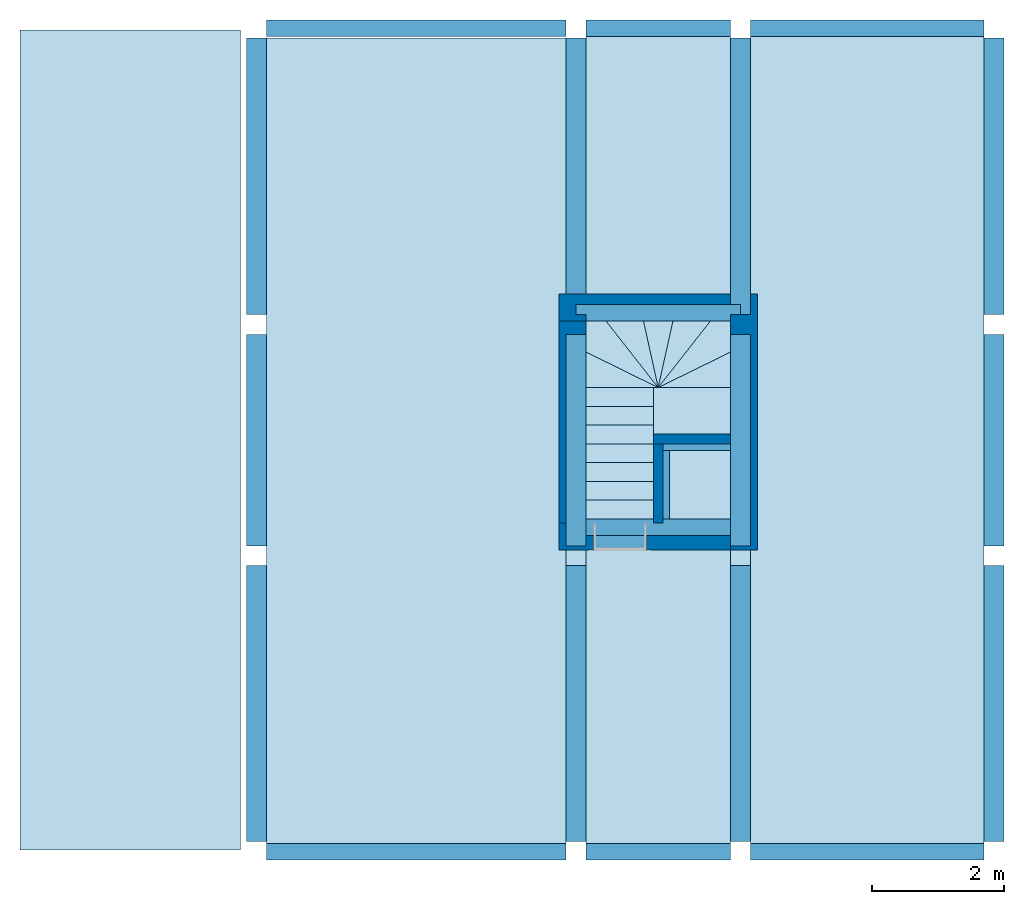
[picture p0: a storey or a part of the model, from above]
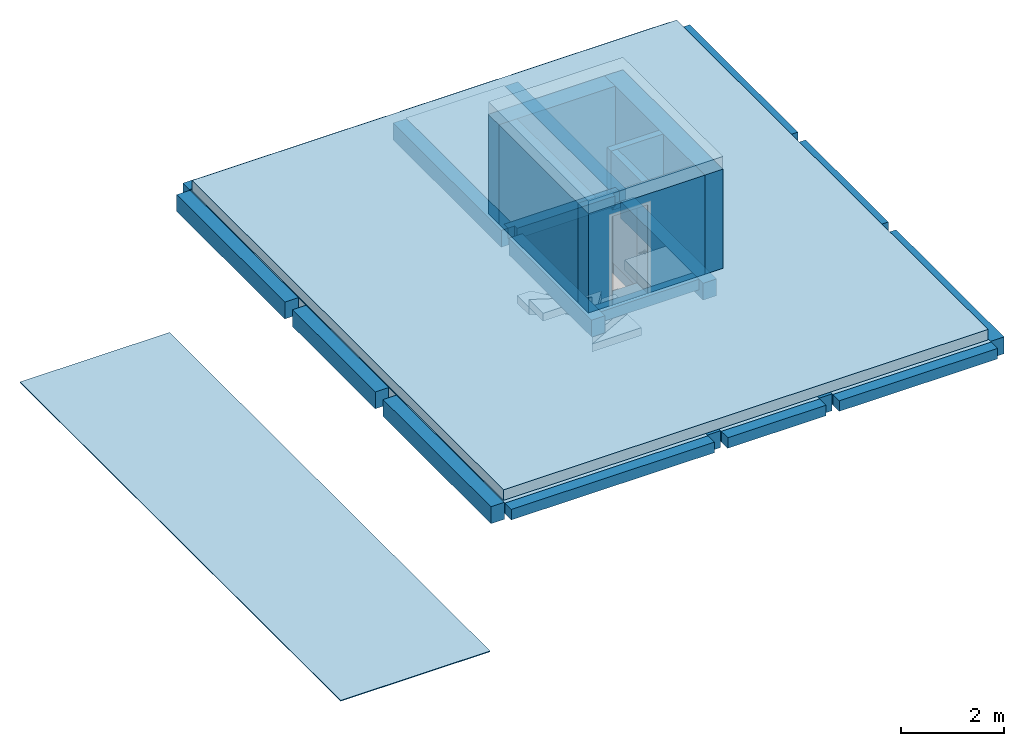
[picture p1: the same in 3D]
Properties of the parts of a building model (IFC2X3), part 1 of 2

# File
Description: ViewDefinition [CoordinationView]
File name: 0001
Time: 2017-05-10T12:55:04
Written by: The EXPRESS Data Manager Version 5.02.0100.07 : 28 Aug 2013
Made in: 20150714_1515(x64) - Exporter 16.0.490.0 - Default UI
Comment: STEP Physical File produced by: The EXPRESS Data Manager Version 5.02.0100.07 : 28 Aug 2013 * Module: EDMstepFileFactory/EDMstandAlone * Creation date: Wed May 10 12:55:04 2017 * Host: w8-delineacion7 * Database: C:\Users\INGENI~1\AppData\Local\Temp\{9E7FC245-E9FD-45FD-B6C2-730FFDB07C34}\ifc * Database version: 5507 * Database creation date: Wed May 10 12:55:01 2017 * Schema: IFC2X3 * Model: DataRepository.ifc * Model creation date: Wed May 10 12:55:01 2017 * Header model: DataRepository.ifc_HeaderModel * Header model creation date: Wed May 10 12:55:01 2017 * EDMuser: sdai-user * EDMgroup: sdai-group * License ID and type: 5605 : Permanent license. Expiry date: * EDMstepFileFactory options: 020000

# IfcProject, 0001
LongName: Nombre de proyecto; Phase: Estado de proyecto

# IfcSite, Default
RefLatitude: 40, 24, 0, 5493; RefLongitude: -3, -40, -59, -880065; RefElevation: 0 m
Otros - Categoría: Información de proyecto; Dirección de proyecto: Introduzca dirección aquí; Estado de proyecto: Estado de proyecto; Fecha de emisión de proyecto: Fecha de emisión; Nombre de cliente: Propietario; Nombre de proyecto: Nombre de proyecto; Número de proyecto: 0001

# IfcBuilding
Pset_BuildingCommon - NumberOfStoreys: 6
Otros - Categoría: Información de proyecto; Dirección de proyecto: Introduzca dirección aquí; Estado de proyecto: Estado de proyecto; Fecha de emisión de proyecto: Fecha de emisión; Nombre de cliente: Propietario; Nombre de proyecto: Nombre de proyecto; Número de proyecto: 0001

# IfcBuildingStorey (6)
Cotas - Altura de cálculo: 0 m
Datos de identidad - Estructura: no; Planta de edificio: yes; Nombre de tipo: Nivel 1
Otros - Categoría: Niveles; Familia: Nivel: Nivel 1; Familia y tipo: Nivel: Nivel 1; ID de tipo: Nivel: Nivel 1; Tipo: Nivel: Nivel 1; Nombre de familia: Nivel
Gráficos - Color: 0; Grosor de línea: 1; Patrón de línea: Trazo punto; Símbolo: Extremo de nivel: Extremo de nivel; Símbolo en extremo 1 por defecto: no; Símbolo en extremo 2 por defecto: yes
Restricciones - Altura base: Punto base del proyecto
Name | LongName = Nombre | Elevation (m) = Alzado (m)
00.ES.CIMENTACIÓN | 00.ES.CIMENTACIÓN | -0.68
01.ES.FORJADO PLANTA BAJA | 01.ES.FORJADO PLANTA BAJA | 0.12
01.AR.PLANTA BAJA ACAB.SUELO | 01.AR.PLANTA BAJA ACAB.SUELO | 0.2
02.ES.PLANTA PRIMERA | 02.ES.PLANTA PRIMERA | 3.45
02.AR.PLANTA PRIMERA ACAB. SUELO | 02.AR.PLANTA PRIMERA ACAB. SUELO | 3.53
03.ES.CUBIERTA | 03.ES.CUBIERTA | 6.78

# IfcBeam: Hormigón-Viga rectangular:250 x 250 mm:155761 (23)
Pset_BeamCommon - IsExternal: no; LoadBearing: yes; Slope: 0 deg; Reference: 250 x 250 mm
Estructura - Activar modelo analítico: yes; Recubrimiento de armadura - Cara inferior: Configuración de recubrimiento de armadura: Revestimiento de armadura 1; Recubrimiento de armadura - Cara superior: Configuración de recubrimiento de armadura: Revestimiento de armadura 1; Recubrimiento de armadura - Otras caras: Configuración de recubrimiento de armadura: Revestimiento de armadura 1; Forma de sección: 0
Otros - Categoría: Armazón estructural; Familia: Hormigón-Viga rectangular: 250 x 250 mm; Familia y tipo: Hormigón-Viga rectangular: 250 x 250 mm; ID de tipo: Hormigón-Viga rectangular: 250 x 250 mm; Tipo: Hormigón-Viga rectangular: 250 x 250 mm; Nombre de familia: Hormigón-Viga rectangular
Posición geométrica - Estado de unión: Ambas uniones activadas; Justificación Y: Origen; Justificación YZ: Uniforme; Justificación Z: Parte superior; Valor de desfase Y: 0 m; Valor de desfase Z: 0 m
Proceso por fases - Fase de creación: Nueva construcción
Restricciones - Desfase de nivel final: 0 m; Desfase de nivel inicial: 0 m; Orientación: Normal; Rotación de sección transversal: 0 deg
Cotas - b: 0.25 m; h: 0.25 m
Datos de identidad - Nombre de tipo: 250 x 250 mm
Name (Hormigón-Viga rectangular:250 x 250 mm:...) | In | Span (m) = Longitud (m) | Área (m2) | Elevación en parte inferior (m) | Elevación en parte superior (m) = Elevación de nivel de referencia (m) | Volumen (m3) | Longitud de corte (m) | Tipo de enlace final = Tipo de enlace inicial | Uso estructural | Nivel de referencia | Plano de trabajo
155414 | 02.ES.PLANTA PRIMERA | 4.24 | 2.18253 | 3.2 | 3.45 | 0.265004 | 4.24006 | Elevación final | Jácena | Nivel: 02.ES.PLANTA PRIMERA | Nivel : 02.ES.PLANTA PRIMERA
155586 | 02.ES.PLANTA PRIMERA | 3.26 | 1.69247 | 3.2 | 3.45 | 0.203746 | 3.25994 | Elevación final | Jácena | Nivel: 02.ES.PLANTA PRIMERA | Nivel : 02.ES.PLANTA PRIMERA
155618 | 02.ES.PLANTA PRIMERA | 4.25 | 2.1875 | 3.2 | 3.45 | 0.265625 | 4.25 | Elevación final | Jácena | Nivel: 02.ES.PLANTA PRIMERA | Nivel : 02.ES.PLANTA PRIMERA
155778 | 02.ES.PLANTA PRIMERA | 3.34 | 1.7325 | 3.2 | 3.45 | 0.20875 | 3.34 | Elevación final | Jácena | Nivel: 02.ES.PLANTA PRIMERA | Nivel : 02.ES.PLANTA PRIMERA
155796 | 02.ES.PLANTA PRIMERA | 4.55 | 2.3375 | 3.2 | 3.45 | 0.284375 | 4.55 | Elevación final | Jácena | Nivel: 02.ES.PLANTA PRIMERA | Nivel : 02.ES.PLANTA PRIMERA
155823 | 02.ES.PLANTA PRIMERA | 2.2 | 1.1625 | 3.2 | 3.45 | 0.1375 | 2.2 | Elevación final | Jácena | Nivel: 02.ES.PLANTA PRIMERA | Nivel : 02.ES.PLANTA PRIMERA
155849 | 02.ES.PLANTA PRIMERA | 3.55 | 1.8375 | 3.2 | 3.45 | 0.221875 | 3.55 | Elevación final | Jácena | Nivel: 02.ES.PLANTA PRIMERA | Nivel : 02.ES.PLANTA PRIMERA
155918 | 02.ES.PLANTA PRIMERA | 3.34 | 1.7325 | 3.2 | 3.45 | 0.20875 | 3.34 | Elevación final | Jácena | Nivel: 02.ES.PLANTA PRIMERA | Nivel : 02.ES.PLANTA PRIMERA
155951 | 02.ES.PLANTA PRIMERA | 4.55 | 2.3375 | 3.2 | 3.45 | 0.284375 | 4.55 | Elevación final | Jácena | Nivel: 02.ES.PLANTA PRIMERA | Nivel : 02.ES.PLANTA PRIMERA
155977 | 02.ES.PLANTA PRIMERA | 2.2 | 1.1625 | 3.2 | 3.45 | 0.1375 | 2.2 | Elevación final | Jácena | Nivel: 02.ES.PLANTA PRIMERA | Nivel : 02.ES.PLANTA PRIMERA
156023 | 02.ES.PLANTA PRIMERA | 3.55 | 1.8375 | 3.2 | 3.45 | 0.221875 | 3.55 | Elevación final | Jácena | Nivel: 02.ES.PLANTA PRIMERA | Nivel : 02.ES.PLANTA PRIMERA
156058 | 02.ES.PLANTA PRIMERA | 2.5 | 1.1625 | 3.2 | 3.45 | 0.1375 | 2.2 |  | Vigueta | Nivel: 02.ES.PLANTA PRIMERA | Nivel : 02.ES.PLANTA PRIMERA
156088 | 02.ES.PLANTA PRIMERA | 2.2 | 1.1625 | 3.2 | 3.45 | 0.1375 | 2.2 | Elevación final | Jácena | Nivel: 02.ES.PLANTA PRIMERA | Nivel : 02.ES.PLANTA PRIMERA
156848 | 03.ES.CUBIERTA | 3.55 | 1.8375 | 6.53 | 6.78 | 0.221875 | 3.55 | Elevación final | Jácena | Nivel: 03.ES.CUBIERTA | Nivel : 03.ES.CUBIERTA
156881 | 03.ES.CUBIERTA | 2.2 | 1.1625 | 6.53 | 6.78 | 0.1375 | 2.2 | Elevación final | Jácena | Nivel: 03.ES.CUBIERTA | Nivel : 03.ES.CUBIERTA
156908 | 03.ES.CUBIERTA | 4.55 | 2.3375 | 6.53 | 6.78 | 0.284375 | 4.55 | Elevación final | Jácena | Nivel: 03.ES.CUBIERTA | Nivel : 03.ES.CUBIERTA
156937 | 03.ES.CUBIERTA | 3.55 | 1.8375 | 6.53 | 6.78 | 0.221875 | 3.55 | Elevación final | Jácena | Nivel: 03.ES.CUBIERTA | Nivel : 03.ES.CUBIERTA
156961 | 03.ES.CUBIERTA | 2.2 | 1.1625 | 6.53 | 6.78 | 0.1375 | 2.2 | Elevación final | Jácena | Nivel: 03.ES.CUBIERTA | Nivel : 03.ES.CUBIERTA
156997 | 03.ES.CUBIERTA | 4.55 | 2.3375 | 6.53 | 6.78 | 0.284375 | 4.55 | Elevación final | Jácena | Nivel: 03.ES.CUBIERTA | Nivel : 03.ES.CUBIERTA
157406 | 03.ES.CUBIERTA | 2.5 | 1.1625 | 6.53 | 6.78 | 0.1375 | 2.2 |  | Vigueta | Nivel: 03.ES.CUBIERTA | Nivel : 03.ES.CUBIERTA
157472 | 03.ES.CUBIERTA | 1.2 | 0.65 | 6.53 | 6.78 | 0.0734375 | 1.175 |  | Otro | Nivel: 03.ES.CUBIERTA | Nivel : 03.ES.CUBIERTA
157499 | 03.ES.CUBIERTA | 1.29 | 0.5825 | 6.53 | 6.78 | 0.065 | 1.04 |  | Otro | Nivel: 03.ES.CUBIERTA | Nivel : 03.ES.CUBIERTA
157592 | 03.ES.CUBIERTA | 2.5 | 1.284 | 6.53 | 6.78 | 0.149125 | 2.5 | Elevación final | Vigueta | Nivel: 03.ES.CUBIERTA | Nivel : 03.ES.CUBIERTA

# IfcBeam: Hormigón-Viga rectangular:300 x 400 mm:155521 (24)
Pset_BeamCommon - IsExternal: no; LoadBearing: yes; Slope: 0 deg; Reference: 300 x 400 mm
Estructura - Activar modelo analítico: yes; Recubrimiento de armadura - Cara inferior: Configuración de recubrimiento de armadura: Revestimiento de armadura 1; Recubrimiento de armadura - Cara superior: Configuración de recubrimiento de armadura: Revestimiento de armadura 1; Recubrimiento de armadura - Otras caras: Configuración de recubrimiento de armadura: Revestimiento de armadura 1; Tipo de enlace final: Elevación final; Tipo de enlace inicial: Elevación final; Uso estructural: Jácena; Forma de sección: 0
Otros - Categoría: Armazón estructural; Familia: Hormigón-Viga rectangular: 300 x 400 mm; Familia y tipo: Hormigón-Viga rectangular: 300 x 400 mm; ID de tipo: Hormigón-Viga rectangular: 300 x 400 mm; Tipo: Hormigón-Viga rectangular: 300 x 400 mm; Nombre de familia: Hormigón-Viga rectangular
Posición geométrica - Estado de unión: Ambas uniones activadas; Justificación Y: Origen; Justificación YZ: Uniforme; Justificación Z: Parte superior; Valor de desfase Y: 0 m; Valor de desfase Z: 0 m
Proceso por fases - Fase de creación: Nueva construcción
Restricciones - Desfase de nivel final: 0 m; Desfase de nivel inicial: 0 m; Orientación: Normal; Rotación de sección transversal: 0 deg
Cotas - b: 0.3 m; h: 0.4 m
Datos de identidad - Nombre de tipo: 300 x 400 mm
Name (Hormigón-Viga rectangular:300 x 400 mm:...) | In | Span (m) = Longitud (m) | Área (m2) | Elevación en parte inferior (m) | Elevación en parte superior (m) = Elevación de nivel de referencia (m) | Volumen (m3) | Longitud de corte (m) | Nivel de referencia | Plano de trabajo
155697 | 02.ES.PLANTA PRIMERA | 4.24 | 3.05304 | 3.05 | 3.45 | 0.502807 | 4.19006 | Nivel: 02.ES.PLANTA PRIMERA | Nivel : 02.ES.PLANTA PRIMERA
155699 | 02.ES.PLANTA PRIMERA | 3.26 | 2.36696 | 3.05 | 3.45 | 0.385193 | 3.20994 | Nivel: 02.ES.PLANTA PRIMERA | Nivel : 02.ES.PLANTA PRIMERA
155701 | 02.ES.PLANTA PRIMERA | 4.25 | 3.06 | 3.05 | 3.45 | 0.504 | 4.2 | Nivel: 02.ES.PLANTA PRIMERA | Nivel : 02.ES.PLANTA PRIMERA
155718 | 02.ES.PLANTA PRIMERA | 4.24 | 3.05304 | 3.05 | 3.45 | 0.502807 | 4.19006 | Nivel: 02.ES.PLANTA PRIMERA | Nivel : 02.ES.PLANTA PRIMERA
155720 | 02.ES.PLANTA PRIMERA | 3.26 | 2.36696 | 3.05 | 3.45 | 0.385193 | 3.20994 | Nivel: 02.ES.PLANTA PRIMERA | Nivel : 02.ES.PLANTA PRIMERA
155722 | 02.ES.PLANTA PRIMERA | 4.25 | 3.06 | 3.05 | 3.45 | 0.504 | 4.2 | Nivel: 02.ES.PLANTA PRIMERA | Nivel : 02.ES.PLANTA PRIMERA
155730 | 02.ES.PLANTA PRIMERA | 4.24 | 3.05304 | 3.05 | 3.45 | 0.502807 | 4.19006 | Nivel: 02.ES.PLANTA PRIMERA | Nivel : 02.ES.PLANTA PRIMERA
155732 | 02.ES.PLANTA PRIMERA | 3.26 | 2.36696 | 3.05 | 3.45 | 0.385193 | 3.20994 | Nivel: 02.ES.PLANTA PRIMERA | Nivel : 02.ES.PLANTA PRIMERA
155734 | 02.ES.PLANTA PRIMERA | 4.25 | 3.06 | 3.05 | 3.45 | 0.504 | 4.2 | Nivel: 02.ES.PLANTA PRIMERA | Nivel : 02.ES.PLANTA PRIMERA
155746 | 02.ES.PLANTA PRIMERA | 4.24 | 3.05304 | 3.05 | 3.45 | 0.502807 | 4.19006 | Nivel: 02.ES.PLANTA PRIMERA | Nivel : 02.ES.PLANTA PRIMERA
155748 | 02.ES.PLANTA PRIMERA | 3.26 | 2.36696 | 3.05 | 3.45 | 0.385193 | 3.20994 | Nivel: 02.ES.PLANTA PRIMERA | Nivel : 02.ES.PLANTA PRIMERA
155750 | 02.ES.PLANTA PRIMERA | 4.25 | 3.06 | 3.05 | 3.45 | 0.504 | 4.2 | Nivel: 02.ES.PLANTA PRIMERA | Nivel : 02.ES.PLANTA PRIMERA
157061 | 03.ES.CUBIERTA | 4.19 | 3.05304 | 6.38 | 6.78 | 0.502807 | 4.19006 | Nivel: 03.ES.CUBIERTA | Nivel : 03.ES.CUBIERTA
157082 | 03.ES.CUBIERTA | 3.21 | 2.36696 | 6.38 | 6.78 | 0.385193 | 3.20994 | Nivel: 03.ES.CUBIERTA | Nivel : 03.ES.CUBIERTA
157100 | 03.ES.CUBIERTA | 4.2 | 3.06 | 6.38 | 6.78 | 0.504 | 4.2 | Nivel: 03.ES.CUBIERTA | Nivel : 03.ES.CUBIERTA
157162 | 03.ES.CUBIERTA | 4.19 | 3.05304 | 6.38 | 6.78 | 0.502807 | 4.19006 | Nivel: 03.ES.CUBIERTA | Nivel : 03.ES.CUBIERTA
157164 | 03.ES.CUBIERTA | 3.21 | 2.36696 | 6.38 | 6.78 | 0.385193 | 3.20994 | Nivel: 03.ES.CUBIERTA | Nivel : 03.ES.CUBIERTA
157166 | 03.ES.CUBIERTA | 4.2 | 3.06 | 6.38 | 6.78 | 0.498188 | 4.2 | Nivel: 03.ES.CUBIERTA | Nivel : 03.ES.CUBIERTA
157176 | 03.ES.CUBIERTA | 4.19 | 3.05304 | 6.38 | 6.78 | 0.502807 | 4.19006 | Nivel: 03.ES.CUBIERTA | Nivel : 03.ES.CUBIERTA
157178 | 03.ES.CUBIERTA | 3.21 | 2.36696 | 6.38 | 6.78 | 0.385193 | 3.20994 | Nivel: 03.ES.CUBIERTA | Nivel : 03.ES.CUBIERTA
157180 | 03.ES.CUBIERTA | 4.2 | 3.06 | 6.38 | 6.78 | 0.498188 | 4.2 | Nivel: 03.ES.CUBIERTA | Nivel : 03.ES.CUBIERTA
157188 | 03.ES.CUBIERTA | 4.19 | 3.05304 | 6.38 | 6.78 | 0.502807 | 4.19006 | Nivel: 03.ES.CUBIERTA | Nivel : 03.ES.CUBIERTA
157190 | 03.ES.CUBIERTA | 3.21 | 2.36696 | 6.38 | 6.78 | 0.385193 | 3.20994 | Nivel: 03.ES.CUBIERTA | Nivel : 03.ES.CUBIERTA
157192 | 03.ES.CUBIERTA | 4.2 | 3.06 | 6.38 | 6.78 | 0.504 | 4.2 | Nivel: 03.ES.CUBIERTA | Nivel : 03.ES.CUBIERTA

# IfcBeam: Hormigón-Viga rectangular:600 x 700 mm:151253 (31)
In: 00.ES.CIMENTACIÓN
Material: Hormigón - Hormigón moldeado in situ
Pset_BeamCommon - IsExternal: no; LoadBearing: yes; Reference: 600 x 700 mm; Slope: 0 deg
Cotas - Elevación en parte inferior: -1.38 m; Elevación en parte superior: -0.68 m; b: 0.6 m; h: 0.7 m
Estructura - Activar modelo analítico: yes; Recubrimiento de armadura - Cara inferior: Configuración de recubrimiento de armadura: Revestimiento de armadura 1; Recubrimiento de armadura - Cara superior: Configuración de recubrimiento de armadura: Revestimiento de armadura 1; Recubrimiento de armadura - Otras caras: Configuración de recubrimiento de armadura: Revestimiento de armadura 1; Uso estructural: Otro; Forma de sección: 0
Otros - Categoría: Armazón estructural; Familia: Hormigón-Viga rectangular: 600 x 700 mm; Familia y tipo: Hormigón-Viga rectangular: 600 x 700 mm; ID de tipo: Hormigón-Viga rectangular: 600 x 700 mm; Tipo: Hormigón-Viga rectangular: 600 x 700 mm; Nombre de familia: Hormigón-Viga rectangular
Posición geométrica - Estado de unión: Ambas uniones activadas; Justificación Y: Origen; Justificación YZ: Uniforme; Justificación Z: Parte superior; Valor de desfase Y: 0 m; Valor de desfase Z: 0 m
Proceso por fases - Fase de creación: Nueva construcción
Restricciones - Desfase de nivel final: 0 m; Desfase de nivel inicial: 0 m; Elevación de nivel de referencia: -0.68 m; Nivel de referencia: Nivel: 00.ES.CIMENTACIÓN; Orientación: Normal; Plano de trabajo: Nivel : 00.ES.CIMENTACIÓN; Rotación de sección transversal: 0 deg
Datos de identidad - Nombre de tipo: 600 x 700 mm
Name (Hormigón-Viga rectangular:600 x 700 mm:...) | Span (m) = Longitud (m) | Área (m2) | Volumen (m3) | Longitud de corte (m)
151318 | 2.35 | 3.475 | 0.987 | 2.35
151368 | 1 | 1.72 | 0.42 | 1
151405 | 3.35 | 4.775 | 1.407 | 3.35
151619 | 2.265 | 3.3645 | 0.9513 | 2.265
151684 | 3.29 | 4.69708 | 1.38183 | 3.29006
151724 | 2.309 | 3.42292 | 0.970174 | 2.30994
151781 | 3.3 | 4.71 | 1.386 | 3.3
151873 | 2.35 | 3.475 | 0.987 | 2.35
151875 | 1 | 1.72 | 0.42 | 1
151877 | 3.35 | 4.775 | 1.407 | 3.35
151879 | 2.265 | 3.3645 | 0.9513 | 2.265
151904 | 2.35 | 3.475 | 0.987 | 2.35
151906 | 1 | 1.72 | 0.42 | 1
151908 | 3.35 | 4.775 | 1.407 | 3.35
151910 | 2.265 | 3.3645 | 0.9513 | 2.265
151935 | 2.35 | 3.475 | 0.987 | 2.35
151937 | 1 | 1.72 | 0.42 | 1
151939 | 3.35 | 4.775 | 1.407 | 3.35
151941 | 2.265 | 3.3645 | 0.9513 | 2.265
151996 | 3.29 | 4.30708 | 1.25583 | 2.99006
151998 | 2.309 | 3.03292 | 0.844174 | 2.00994
152000 | 3.3 | 4.32 | 1.26 | 3
152021 | 3.29 | 4.30708 | 1.25583 | 2.99006
152023 | 2.309 | 3.03292 | 0.844174 | 2.00994
152025 | 3.3 | 4.32 | 1.26 | 3
152046 | 3.29 | 4.30708 | 1.25583 | 2.99006
152048 | 2.309 | 3.03292 | 0.844174 | 2.00994
152050 | 3.3 | 4.32 | 1.26 | 3
152073 | 3.29 | 4.30708 | 1.25583 | 2.99006
152075 | 2.309 | 3.03292 | 0.844174 | 2.00994
152077 | 3.3 | 4.32 | 1.26 | 3

# IfcColumn: 250 x 250 mm (4)
In: 00.ES.CIMENTACIÓN
Type - ElementType: 250 x 250 mm; PredefinedType: COLUMN
Type - Cotas - b: 0.25 m; h: 0.25 m
Type - Datos de identidad - Nombre de tipo: 250 x 250 mm
Type - Estructura - Forma de sección: 0
Type - Otros - Categoría: Pilares estructurales; Nombre de familia: Pilar rectangular hormigón
Pset_ColumnCommon - IsExternal: no; LoadBearing: yes; Slope: 0 deg; Reference: 250 x 250 mm
Cotas - Área: 2.1275 m2; Longitud: 4.13 m; Volumen: 0.258125 m3
Estructura - Activar modelo analítico: yes; Recubrimiento de armadura - Cara inferior: Configuración de recubrimiento de armadura: Revestimiento de armadura 1; Recubrimiento de armadura - Cara superior: Configuración de recubrimiento de armadura: Revestimiento de armadura 1; Recubrimiento de armadura - Otras caras: Configuración de recubrimiento de armadura: Revestimiento de armadura 1
Otros - Familia: Pilar rectangular hormigón: 250 x 250 mm; Familia y tipo: Pilar rectangular hormigón: 250 x 250 mm; ID de tipo: Pilar rectangular hormigón: 250 x 250 mm; Tipo: Pilar rectangular hormigón: 250 x 250 mm
Proceso por fases - Fase de creación: Nueva construcción
Restricciones - Se mueve con rejillas: yes; Nivel: Nivel: 00.ES.CIMENTACIÓN; Delimitación de habitación: yes; Desfase de base: 0 m; Desfase superior: 0 m; Estilo de pilar: Vertical; Nivel base: Nivel: 00.ES.CIMENTACIÓN; Nivel superior: Nivel: 02.ES.PLANTA PRIMERA
Name (Pilar rectangular hormigón:250 x 250 mm:...) | Marca de ubicación de pilar
153593 | A-1
153595 | A-2
153597 | A-3
153599 | A-4

# IfcColumn: 300 x 300 mm (32)
Type - ElementType: 300 x 300 mm; PredefinedType: COLUMN
Type - Cotas - b: 0.3 m; h: 0.3 m
Type - Datos de identidad - Nombre de tipo: 300 x 300 mm
Type - Estructura - Forma de sección: 0
Type - Otros - Categoría: Pilares estructurales; Nombre de familia: Pilar rectangular hormigón
Pset_ColumnCommon - IsExternal: no; LoadBearing: yes; Slope: 0 deg; Reference: 300 x 300 mm
Estructura - Activar modelo analítico: yes; Recubrimiento de armadura - Cara inferior: Configuración de recubrimiento de armadura: Revestimiento de armadura 1; Recubrimiento de armadura - Cara superior: Configuración de recubrimiento de armadura: Revestimiento de armadura 1; Recubrimiento de armadura - Otras caras: Configuración de recubrimiento de armadura: Revestimiento de armadura 1
Otros - Familia: Pilar rectangular hormigón: 300 x 300 mm; Familia y tipo: Pilar rectangular hormigón: 300 x 300 mm; ID de tipo: Pilar rectangular hormigón: 300 x 300 mm; Tipo: Pilar rectangular hormigón: 300 x 300 mm
Proceso por fases - Fase de creación: Nueva construcción
Restricciones - Se mueve con rejillas: yes; Delimitación de habitación: yes; Desfase de base: 0 m; Desfase superior: 0 m; Estilo de pilar: Vertical
Name (Pilar rectangular hormigón:300 x 300 mm:...) | In | Área (m2) | Longitud (m) | Volumen (m3) | Nivel = Nivel base | Nivel superior | Marca de ubicación de pilar
153704 | 00.ES.CIMENTACIÓN | 2.568 | 4.13 | 0.3717 | Nivel: 00.ES.CIMENTACIÓN | Nivel: 02.ES.PLANTA PRIMERA | B-1
153706 | 00.ES.CIMENTACIÓN | 2.568 | 4.13 | 0.3717 | Nivel: 00.ES.CIMENTACIÓN | Nivel: 02.ES.PLANTA PRIMERA | C-1
153708 | 00.ES.CIMENTACIÓN | 2.568 | 4.13 | 0.3717 | Nivel: 00.ES.CIMENTACIÓN | Nivel: 02.ES.PLANTA PRIMERA | D-1
153710 | 00.ES.CIMENTACIÓN | 2.568 | 4.13 | 0.3717 | Nivel: 00.ES.CIMENTACIÓN | Nivel: 02.ES.PLANTA PRIMERA | E-1
153712 | 00.ES.CIMENTACIÓN | 2.568 | 4.13 | 0.3717 | Nivel: 00.ES.CIMENTACIÓN | Nivel: 02.ES.PLANTA PRIMERA | B-2
153714 | 00.ES.CIMENTACIÓN | 2.568 | 4.13 | 0.3717 | Nivel: 00.ES.CIMENTACIÓN | Nivel: 02.ES.PLANTA PRIMERA | C-2
153716 | 00.ES.CIMENTACIÓN | 2.568 | 4.13 | 0.3717 | Nivel: 00.ES.CIMENTACIÓN | Nivel: 02.ES.PLANTA PRIMERA | D-2
153718 | 00.ES.CIMENTACIÓN | 2.568 | 4.13 | 0.3717 | Nivel: 00.ES.CIMENTACIÓN | Nivel: 02.ES.PLANTA PRIMERA | E-2
153720 | 00.ES.CIMENTACIÓN | 2.568 | 4.13 | 0.3717 | Nivel: 00.ES.CIMENTACIÓN | Nivel: 02.ES.PLANTA PRIMERA | B-3
153722 | 00.ES.CIMENTACIÓN | 2.568 | 4.13 | 0.3717 | Nivel: 00.ES.CIMENTACIÓN | Nivel: 02.ES.PLANTA PRIMERA | C-3
153724 | 00.ES.CIMENTACIÓN | 2.568 | 4.13 | 0.3717 | Nivel: 00.ES.CIMENTACIÓN | Nivel: 02.ES.PLANTA PRIMERA | D-3
153726 | 00.ES.CIMENTACIÓN | 2.568 | 4.13 | 0.3717 | Nivel: 00.ES.CIMENTACIÓN | Nivel: 02.ES.PLANTA PRIMERA | E-3
153728 | 00.ES.CIMENTACIÓN | 2.568 | 4.13 | 0.3717 | Nivel: 00.ES.CIMENTACIÓN | Nivel: 02.ES.PLANTA PRIMERA | B-4
153730 | 00.ES.CIMENTACIÓN | 2.568 | 4.13 | 0.3717 | Nivel: 00.ES.CIMENTACIÓN | Nivel: 02.ES.PLANTA PRIMERA | C-4
153732 | 00.ES.CIMENTACIÓN | 2.568 | 4.13 | 0.3717 | Nivel: 00.ES.CIMENTACIÓN | Nivel: 02.ES.PLANTA PRIMERA | D-4
153734 | 00.ES.CIMENTACIÓN | 2.568 | 4.13 | 0.3717 | Nivel: 00.ES.CIMENTACIÓN | Nivel: 02.ES.PLANTA PRIMERA | E-4
156709 | 02.ES.PLANTA PRIMERA | 2.088 | 3.33 | 0.2997 | Nivel: 02.ES.PLANTA PRIMERA | Nivel: 03.ES.CUBIERTA | B-1
156711 | 02.ES.PLANTA PRIMERA | 2.088 | 3.33 | 0.2997 | Nivel: 02.ES.PLANTA PRIMERA | Nivel: 03.ES.CUBIERTA | C-1
156713 | 02.ES.PLANTA PRIMERA | 2.088 | 3.33 | 0.2997 | Nivel: 02.ES.PLANTA PRIMERA | Nivel: 03.ES.CUBIERTA | D-1
156715 | 02.ES.PLANTA PRIMERA | 2.088 | 3.33 | 0.2997 | Nivel: 02.ES.PLANTA PRIMERA | Nivel: 03.ES.CUBIERTA | E-1
156717 | 02.ES.PLANTA PRIMERA | 2.088 | 3.33 | 0.2997 | Nivel: 02.ES.PLANTA PRIMERA | Nivel: 03.ES.CUBIERTA | B-2
156719 | 02.ES.PLANTA PRIMERA | 2.088 | 3.33 | 0.2997 | Nivel: 02.ES.PLANTA PRIMERA | Nivel: 03.ES.CUBIERTA | C-2
156721 | 02.ES.PLANTA PRIMERA | 2.088 | 3.33 | 0.2997 | Nivel: 02.ES.PLANTA PRIMERA | Nivel: 03.ES.CUBIERTA | D-2
156723 | 02.ES.PLANTA PRIMERA | 2.088 | 3.33 | 0.2997 | Nivel: 02.ES.PLANTA PRIMERA | Nivel: 03.ES.CUBIERTA | E-2
156725 | 02.ES.PLANTA PRIMERA | 2.088 | 3.33 | 0.2997 | Nivel: 02.ES.PLANTA PRIMERA | Nivel: 03.ES.CUBIERTA | B-3
156727 | 02.ES.PLANTA PRIMERA | 2.088 | 3.33 | 0.2997 | Nivel: 02.ES.PLANTA PRIMERA | Nivel: 03.ES.CUBIERTA | C-3
156729 | 02.ES.PLANTA PRIMERA | 2.088 | 3.33 | 0.2997 | Nivel: 02.ES.PLANTA PRIMERA | Nivel: 03.ES.CUBIERTA | D-3
156731 | 02.ES.PLANTA PRIMERA | 2.088 | 3.33 | 0.2997 | Nivel: 02.ES.PLANTA PRIMERA | Nivel: 03.ES.CUBIERTA | E-3
156733 | 02.ES.PLANTA PRIMERA | 2.088 | 3.33 | 0.2997 | Nivel: 02.ES.PLANTA PRIMERA | Nivel: 03.ES.CUBIERTA | B-4
156735 | 02.ES.PLANTA PRIMERA | 2.088 | 3.33 | 0.2997 | Nivel: 02.ES.PLANTA PRIMERA | Nivel: 03.ES.CUBIERTA | C-4
156737 | 02.ES.PLANTA PRIMERA | 2.088 | 3.33 | 0.2997 | Nivel: 02.ES.PLANTA PRIMERA | Nivel: 03.ES.CUBIERTA | D-4
156739 | 02.ES.PLANTA PRIMERA | 2.088 | 3.33 | 0.2997 | Nivel: 02.ES.PLANTA PRIMERA | Nivel: 03.ES.CUBIERTA | E-4

# IfcCovering: Techo compuesto:Falso techo continuo de placa de yeso laminado (16)
PredefinedType: CEILING; Material: Metal - Perfiles de acero galvanizado 0.045 m, Placa de yeso laminado 0.015 m
Pset_CoveringCommon - Reference: Falso techo continuo de placa de yeso laminado; Finish: Placa de yeso laminado;; TotalThickness: 0.06 m
Otros - Categoría: Techos; Familia: Techo compuesto: Falso techo continuo de placa de yeso laminado; Familia y tipo: Techo compuesto: Falso techo continuo de placa de yeso laminado; ID de tipo: Techo compuesto: Falso techo continuo de placa de yeso laminado; Tipo: Techo compuesto: Falso techo continuo de placa de yeso laminado; Nombre de familia: Techo compuesto
Proceso por fases - Fase de creación: Nueva construcción
Restricciones - Delimitación de habitación: yes; Desfase de altura desde nivel: 2.6 m
Construcción - Grosor: 0.06 m
Datos de identidad - Nombre de tipo: Falso techo continuo de placa de yeso laminado
Gráficos - Color de relleno de detalle bajo: 0
Propiedades analíticas - Aspereza: 3; Absortancia: 0.7
Name (Techo compuesto:Falso techo continuo de placa de yeso laminado:...) | In | Área (m2) | Perímetro (m) | Volumen (m3) | Nivel
181849 | 01.AR.PLANTA BAJA ACAB.SUELO | 4.7957 | 8.76 | 0.287742 | Nivel: 01.AR.PLANTA BAJA ACAB.SUELO
181857 | 01.AR.PLANTA BAJA ACAB.SUELO | 28.821 | 22.99 | 1.72926 | Nivel: 01.AR.PLANTA BAJA ACAB.SUELO
181865 | 01.AR.PLANTA BAJA ACAB.SUELO | 15.3029 | 15.673 | 0.918174 | Nivel: 01.AR.PLANTA BAJA ACAB.SUELO
181873 | 01.AR.PLANTA BAJA ACAB.SUELO | 5.86229 | 9.74304 | 0.351738 | Nivel: 01.AR.PLANTA BAJA ACAB.SUELO
181881 | 01.AR.PLANTA BAJA ACAB.SUELO | 2.7125 | 6.84 | 0.16275 | Nivel: 01.AR.PLANTA BAJA ACAB.SUELO
181889 | 01.AR.PLANTA BAJA ACAB.SUELO | 56.7697 | 33.573 | 3.40618 | Nivel: 01.AR.PLANTA BAJA ACAB.SUELO
181897 | 01.AR.PLANTA BAJA ACAB.SUELO | 56.7697 | 33.573 | 3.40618 | Nivel: 01.AR.PLANTA BAJA ACAB.SUELO
181914 | 01.AR.PLANTA BAJA ACAB.SUELO | 6.24275 | 10.89 | 0.374565 | Nivel: 01.AR.PLANTA BAJA ACAB.SUELO
182334 | 02.AR.PLANTA PRIMERA ACAB. SUELO | 23.9871 | 21.293 | 1.43923 | Nivel: 02.AR.PLANTA PRIMERA ACAB. SUELO
182344 | 02.AR.PLANTA PRIMERA ACAB. SUELO | 5.94334 | 9.80304 | 0.3566 | Nivel: 02.AR.PLANTA PRIMERA ACAB. SUELO
182404 | 02.AR.PLANTA PRIMERA ACAB. SUELO | 2.75 | 6.9 | 0.165 | Nivel: 02.AR.PLANTA PRIMERA ACAB. SUELO
182412 | 02.AR.PLANTA PRIMERA ACAB. SUELO | 15.7874 | 15.9401 | 0.947245 | Nivel: 02.AR.PLANTA PRIMERA ACAB. SUELO
182420 | 02.AR.PLANTA PRIMERA ACAB. SUELO | 30.1591 | 22.6401 | 1.80955 | Nivel: 02.AR.PLANTA PRIMERA ACAB. SUELO
182428 | 02.AR.PLANTA PRIMERA ACAB. SUELO | 8.957 | 12.06 | 0.53742 | Nivel: 02.AR.PLANTA PRIMERA ACAB. SUELO
190506 | 02.AR.PLANTA PRIMERA ACAB. SUELO | 17.2985 | 23.048 | 1.03791 | Nivel: 02.AR.PLANTA PRIMERA ACAB. SUELO
191344 | 02.AR.PLANTA PRIMERA ACAB. SUELO | 15.2408 | 15.643 | 0.914447 | Nivel: 02.AR.PLANTA PRIMERA ACAB. SUELO

# IfcCurtainWall: Muro cortina:Muro cortina - simple (5)
In: 01.AR.PLANTA BAJA ACAB.SUELO
Type - Construcción - Función: Exterior; Condición de unión: Sin definir; Incrustar automáticamente: no
Type - Datos de identidad - Nombre de tipo: Muro cortina - simple; Nota clave: Mc.4
Type - Otros - Categoría: Muros; Nombre de familia: Muro cortina
Type - Rejilla horizontal - Ajustar para tamaño de montante: no; Diseño: Ninguno
Type - Rejilla vertical - Ajustar para tamaño de montante: no; Diseño: Ninguno
Pset_CurtainWallCommon - IsExternal: yes; Reference: Muro cortina - simple
Estructura - Activar modelo analítico: no; Estructura: no; Uso estructural: No portante
Otros - Familia: Muro cortina: Muro cortina - simple; Familia y tipo: Muro cortina: Muro cortina - simple; ID de tipo: Muro cortina: Muro cortina - simple; Tipo: Muro cortina: Muro cortina - simple
Proceso por fases - Fase de creación: Nueva construcción
Rejilla horizontal - Desfase: 0 m; Ángulo: 0 deg; Justificación: Inicio; Número: 4; sets with these values: 2
Restricciones - Delimitación de habitación: yes; Desfase de base: 0 m; Desfase superior: 0 m; La base está enlazada: no; La parte superior está enlazada: no; Relacionado con masa: no; Restricción de base: Nivel: 01.AR.PLANTA BAJA ACAB.SUELO; Altura desconectada: 3 m
Name (Muro cortina:Muro cortina - simple:...) | Área (m2) | Longitud (m)
193462 | 9.75 | 3.455
193901 | 12.7202 | 4.24006
194046 | 9.77982 | 3.25994
194191 | 12.75 | 4.25
194256 | 9.75 | 3.455

# IfcDoor: 1400 x 2100mm, Puerta practicable de entrada, 2 hojas:1400 x 2100mm:189911
In: 01.AR.PLANTA BAJA ACAB.SUELO
Type - ParameterTakesPrecedence: no; Sizeable: no; Material: Dark Oak, Vidrio
Type - Construcción - Función: Exterior; Cierre de muro: Por anfitrión
Type - Cotas - Altura: 2.1 m; Altura aproximada: 2.1 m; Anchura: 1.4 m; Anchura aproximada: 1.4 m; Anchura de cubrejuntas: 0.035 m; Anchura de marco: 0.05 m; Anchura de marco de panel: 0.1 m; Anchura de montante secundario: 0.07 m; Anchura de puerta con tirador: 0.7 m; Anchura de puerta sin tirador: 0.7 m; Grosor de cubrejuntas: 0.005 m; Grosor de marco: 0.045 m
Type - Datos de identidad - Marca de tipo: 9; Nombre de tipo: 1400 x 2100mm; Número OmniClass: 23.30.10.00; Título OmniClass: Doors
Type - Materiales y acabados - Material de marco: Dark Oak
Type - Otros - Categoría: Puertas; Altura Hoja: 2.07 m; Anchura de panel de puerta con tirador: 0.685 m; Anchura de panel de puerta sin tirador: 0.685 m; Desfase: 0.015 m; Nombre de familia: Puerta practicable de entrada, 2 hojas; w: 0.015 m
Type - Propiedades analíticas - Coeficiente de incremento de calor solar: 0; Transmitancia de luz visual: 0; Coeficiente de transferencia de calor (U): 3.7021; Construcción analítica: Metal; Resistencia térmica (R): 0.270117
OverallHeight: 2.1 m; OverallWidth: 1.4 m
Pset_DoorCommon - IsExternal: yes; Reference: 1400 x 2100mm; ThermalTransmittance: 3.7021 kg/K/s3
Cotas - Área: 4.98891 m2; Volumen: 0.0755501 m3
Datos de identidad - Marca: 22
Otros - ID de anfitrión: Muro básico: F3.2; Altura de extremo inicial: 2.1 m; Familia: Puerta practicable de entrada, 2 hojas: 1400 x 2100mm; Familia y tipo: Puerta practicable de entrada, 2 hojas: 1400 x 2100mm; ID de tipo: Puerta practicable de entrada, 2 hojas: 1400 x 2100mm; Tipo: Puerta practicable de entrada, 2 hojas: 1400 x 2100mm
Proceso por fases - Fase de creación: Nueva construcción
Restricciones - Nivel: Nivel: 01.AR.PLANTA BAJA ACAB.SUELO; Altura de antepecho: 0 m

# IfcDoor: 200 x 205 cm - 8 Vidrios repartidos (3)
Type - ParameterTakesPrecedence: no; Sizeable: no; Material: Aberturas - Picaporte Entrada, Aberturas - Vidrio, Dark Oak
Type - Construcción - Función: Interior; Cierre de muro: Por anfitrión
Type - Cotas - Alto Hoja: 2.02 m; Altura: 2.05 m; Ancho hoja: 1.03 m; Anchura: 2 m
Type - Datos de identidad - Marca de tipo: 8; Nombre de tipo: 200 x 205 cm - 8 Vidrios repartidos
Type - Materiales y acabados - Hoja Madera: Dark Oak; Marco Madera: Dark Oak; Picaporte: Aberturas - Picaporte; Vidrio: Aberturas - Vidrio
Type - Otros - Categoría: Puertas; Anchura de marco: 0.075 m; Nombre de familia: Puerta Balcón - 2 hojas corredizas; Proyección marco ext.: 0.025 m; Proyección marco int.: 0.025 m
Type - Propiedades analíticas - Construcción analítica: <Ninguno>
OverallHeight: 2.05 m; OverallWidth: 2 m
Pset_DoorCommon - IsExternal: yes; Reference: 200 x 205 cm - 8 Vidrios repartidos
Cotas - Área: 7.73229 m2; Volumen: 0.159268 m3
Datos de identidad - Marco Exterior: yes; Marco Interior: yes
Otros - Altura de extremo inicial: 2.05 m; Familia: Puerta Balcón - 2 hojas corredizas: 200 x 205 cm - 8 Vidrios repartidos; Familia y tipo: Puerta Balcón - 2 hojas corredizas: 200 x 205 cm - 8 Vidrios repartidos; ID de anfitrión: Muro básico: F3.2; ID de tipo: Puerta Balcón - 2 hojas corredizas: 200 x 205 cm - 8 Vidrios repartidos; Tipo: Puerta Balcón - 2 hojas corredizas: 200 x 205 cm - 8 Vidrios repartidos
Proceso por fases - Fase de creación: Nueva construcción
Restricciones - Altura de antepecho: 0 m
Name (Puerta Balcón - 2 hojas corredizas:200 x 205 cm - 8 Vidrios repartidos:...) | In | Marca | Nivel
180524 | 02.AR.PLANTA PRIMERA ACAB. SUELO | 9 | Nivel: 02.AR.PLANTA PRIMERA ACAB. SUELO
180545 | 02.AR.PLANTA PRIMERA ACAB. SUELO | 10 | Nivel: 02.AR.PLANTA PRIMERA ACAB. SUELO
180603 | 01.AR.PLANTA BAJA ACAB.SUELO | 11 | Nivel: 01.AR.PLANTA BAJA ACAB.SUELO

# IfcDoor: 70 x 210 cm (4)
Type - OperationType: SINGLE_SWING_LEFT; ParameterTakesPrecedence: no; Sizeable: no; Material: Madera - Castaño
Type - Puerta de 1 hoja:70 x 210 cm:175581 - PanelOperation: SWINGING
Type - Construcción - Función: Interior; Cierre de muro: Ambas
Type - Cotas - Altura: 2.1 m; Anchura: 0.7 m
Type - Datos de identidad - Marca de tipo: 4; Nombre de tipo: 70 x 210 cm
Type - Otros - Categoría: Puertas; Nombre de familia: Puerta de 1 hoja
Type - Propiedades analíticas - Coeficiente de incremento de calor solar: 0; Transmitancia de luz visual: 0; Coeficiente de transferencia de calor (U): 3.7021; Construcción analítica: Metal; Resistencia térmica (R): 0.270117
OverallHeight: 2.1 m; OverallWidth: 0.7 m
Pset_DoorCommon - IsExternal: yes; Reference: 70 x 210 cm; ThermalTransmittance: 3.7021 kg/K/s3
Cotas - Área: 2.4301 m2; Volumen: 0.0855295 m3
Otros - ID de anfitrión: Muro básico: Por defecto - 15 cm; Altura de extremo inicial: 2.1 m; Familia: Puerta de 1 hoja: 70 x 210 cm; Familia y tipo: Puerta de 1 hoja: 70 x 210 cm; ID de tipo: Puerta de 1 hoja: 70 x 210 cm; Tipo: Puerta de 1 hoja: 70 x 210 cm
Proceso por fases - Fase de creación: Nueva construcción
Restricciones - Altura de antepecho: 0 m
Name (Puerta de 1 hoja:70 x 210 cm:...) | In | Marca | Nivel
175581 | 01.AR.PLANTA BAJA ACAB.SUELO | 5 | Nivel: 01.AR.PLANTA BAJA ACAB.SUELO
175626 | 01.AR.PLANTA BAJA ACAB.SUELO | 7 | Nivel: 01.AR.PLANTA BAJA ACAB.SUELO
180832 | 02.AR.PLANTA PRIMERA ACAB. SUELO | 17 | Nivel: 02.AR.PLANTA PRIMERA ACAB. SUELO
180849 | 02.AR.PLANTA PRIMERA ACAB. SUELO | 18 | Nivel: 02.AR.PLANTA PRIMERA ACAB. SUELO

# IfcDoor: 70 x 210 cm (3)
Type - OperationType: SINGLE_SWING_RIGHT; ParameterTakesPrecedence: no; Sizeable: no; Material: Madera - Castaño
Type - Construcción - Función: Interior; Cierre de muro: Ambas
Type - Cotas - Altura: 2.1 m; Anchura: 0.7 m
Type - Datos de identidad - Marca de tipo: 4; Nombre de tipo: 70 x 210 cm
Type - Otros - Categoría: Puertas; Nombre de familia: Puerta de 1 hoja
Type - Propiedades analíticas - Coeficiente de incremento de calor solar: 0; Transmitancia de luz visual: 0; Coeficiente de transferencia de calor (U): 3.7021; Construcción analítica: Metal; Resistencia térmica (R): 0.270117
Type - Puerta de 1 hoja:70 x 210 cm:175607 - PanelOperation: SWINGING
OverallHeight: 2.1 m; OverallWidth: 0.7 m
Pset_DoorCommon - IsExternal: yes; Reference: 70 x 210 cm; ThermalTransmittance: 3.7021 kg/K/s3
Cotas - Área: 2.4301 m2; Volumen: 0.0855295 m3
Otros - ID de anfitrión: Muro básico: Por defecto - 15 cm; Familia: Puerta de 1 hoja: 70 x 210 cm; Familia y tipo: Puerta de 1 hoja: 70 x 210 cm; ID de tipo: Puerta de 1 hoja: 70 x 210 cm; Tipo: Puerta de 1 hoja: 70 x 210 cm; Altura de extremo inicial: 2.1 m
Proceso por fases - Fase de creación: Nueva construcción
Restricciones - Altura de antepecho: 0 m
Name (Puerta de 1 hoja:70 x 210 cm:...) | In | Marca | Nivel
175607 | 01.AR.PLANTA BAJA ACAB.SUELO | 6 | Nivel: 01.AR.PLANTA BAJA ACAB.SUELO
180809 | 02.AR.PLANTA PRIMERA ACAB. SUELO | 16 | Nivel: 02.AR.PLANTA PRIMERA ACAB. SUELO
180873 | 02.AR.PLANTA PRIMERA ACAB. SUELO | 19 | Nivel: 02.AR.PLANTA PRIMERA ACAB. SUELO

# IfcDoor: 80 x 210 cm (6)
Type - OperationType: SINGLE_SWING_LEFT; ParameterTakesPrecedence: no; Sizeable: no; Material: Madera - Castaño
Type - Puerta de 1 hoja:80 x 210 cm:174499 - PanelOperation: SWINGING
Type - Construcción - Función: Interior; Cierre de muro: Ambas
Type - Cotas - Altura: 2.1 m; Anchura: 0.8 m
Type - Datos de identidad - Marca de tipo: 1; Nombre de tipo: 80 x 210 cm
Type - Otros - Categoría: Puertas; Nombre de familia: Puerta de 1 hoja
Type - Propiedades analíticas - Coeficiente de incremento de calor solar: 0; Coeficiente de transferencia de calor (U): 3.7021; Construcción analítica: Metal; Resistencia térmica (R): 0.270117; Transmitancia de luz visual: 0
OverallHeight: 2.1 m; OverallWidth: 0.8 m
Pset_DoorCommon - IsExternal: yes; Reference: 80 x 210 cm; ThermalTransmittance: 3.7021 kg/K/s3
Cotas - Área: 2.6631 m2; Volumen: 0.0954695 m3
Otros - Altura de extremo inicial: 2.1 m; Familia: Puerta de 1 hoja: 80 x 210 cm; Familia y tipo: Puerta de 1 hoja: 80 x 210 cm; ID de anfitrión: Muro básico: Por defecto - 15 cm; ID de tipo: Puerta de 1 hoja: 80 x 210 cm; Tipo: Puerta de 1 hoja: 80 x 210 cm
Proceso por fases - Fase de creación: Nueva construcción
Restricciones - Altura de antepecho: 0 m
Name (Puerta de 1 hoja:80 x 210 cm:...) | In | Marca | Nivel
174499 | 01.AR.PLANTA BAJA ACAB.SUELO | 2 | Nivel: 01.AR.PLANTA BAJA ACAB.SUELO
175539 | 01.AR.PLANTA BAJA ACAB.SUELO | 4 | Nivel: 01.AR.PLANTA BAJA ACAB.SUELO
175646 | 01.AR.PLANTA BAJA ACAB.SUELO | 8 | Nivel: 01.AR.PLANTA BAJA ACAB.SUELO
180703 | 02.AR.PLANTA PRIMERA ACAB. SUELO | 12 | Nivel: 02.AR.PLANTA PRIMERA ACAB. SUELO
180754 | 02.AR.PLANTA PRIMERA ACAB. SUELO | 14 | Nivel: 02.AR.PLANTA PRIMERA ACAB. SUELO
185067 | 01.AR.PLANTA BAJA ACAB.SUELO | 21 | Nivel: 01.AR.PLANTA BAJA ACAB.SUELO

# IfcDoor: 80 x 210 cm (4)
Type - OperationType: SINGLE_SWING_RIGHT; ParameterTakesPrecedence: no; Sizeable: no; Material: Madera - Castaño
Type - Construcción - Función: Interior; Cierre de muro: Ambas
Type - Cotas - Altura: 2.1 m; Anchura: 0.8 m
Type - Datos de identidad - Marca de tipo: 1; Nombre de tipo: 80 x 210 cm
Type - Otros - Categoría: Puertas; Nombre de familia: Puerta de 1 hoja
Type - Propiedades analíticas - Coeficiente de incremento de calor solar: 0; Coeficiente de transferencia de calor (U): 3.7021; Construcción analítica: Metal; Resistencia térmica (R): 0.270117; Transmitancia de luz visual: 0
Type - Puerta de 1 hoja:80 x 210 cm:174534 - PanelOperation: SWINGING
OverallHeight: 2.1 m; OverallWidth: 0.8 m
Pset_DoorCommon - IsExternal: yes; Reference: 80 x 210 cm; ThermalTransmittance: 3.7021 kg/K/s3
Cotas - Área: 2.6631 m2; Volumen: 0.0954695 m3
Otros - Familia: Puerta de 1 hoja: 80 x 210 cm; Familia y tipo: Puerta de 1 hoja: 80 x 210 cm; ID de anfitrión: Muro básico: Por defecto - 15 cm; ID de tipo: Puerta de 1 hoja: 80 x 210 cm; Tipo: Puerta de 1 hoja: 80 x 210 cm
Proceso por fases - Fase de creación: Nueva construcción
Name (Puerta de 1 hoja:80 x 210 cm:...) | In | Marca | Altura de extremo inicial (m) | Nivel | Altura de antepecho (m)
174534 | 01.AR.PLANTA BAJA ACAB.SUELO | 3 | 2.1 | Nivel: 01.AR.PLANTA BAJA ACAB.SUELO | 0
180726 | 02.AR.PLANTA PRIMERA ACAB. SUELO | 13 | 2.1 | Nivel: 02.AR.PLANTA PRIMERA ACAB. SUELO | 0
180789 | 02.AR.PLANTA PRIMERA ACAB. SUELO | 15 | 2.1 | Nivel: 02.AR.PLANTA PRIMERA ACAB. SUELO | 0
181129 | 02.AR.PLANTA PRIMERA ACAB. SUELO | 20 | 2.285 | Nivel: 02.AR.PLANTA PRIMERA ACAB. SUELO | 0.185001

# IfcDoor: 80 x 210 cm negra, Puerta de 1 hoja:80 x 210 cm negra:192898
In: 03.ES.CUBIERTA
Type - OperationType: SINGLE_SWING_LEFT; ParameterTakesPrecedence: no; Sizeable: no; Material: Dark Oak, Madera - Castaño
Type - Puerta de 1 hoja:80 x 210 cm negra:192898 - PanelOperation: SWINGING
Type - Construcción - Cierre de muro: Ambas
Type - Cotas - Altura: 2.1 m; Anchura: 0.8 m
Type - Datos de identidad - Marca de tipo: 11; Nombre de tipo: 80 x 210 cm negra
Type - Materiales y acabados - Carpintería: Dark Oak; Hoja: Dark Oak
Type - Otros - Categoría: Puertas; Nombre de familia: Puerta de 1 hoja
Type - Propiedades analíticas - Construcción analítica: <Ninguno>
OverallHeight: 2.1 m; OverallWidth: 0.8 m
Pset_DoorCommon - IsExternal: yes; Reference: 80 x 210 cm negra
Cotas - Área: 3.954 m2; Volumen: 0.140333 m3
Datos de identidad - Marca: 23
Otros - ID de anfitrión: Muro básico: F3.2; Altura de extremo inicial: 2.35 m; Familia: Puerta de 1 hoja: 80 x 210 cm negra; Familia y tipo: Puerta de 1 hoja: 80 x 210 cm negra; ID de tipo: Puerta de 1 hoja: 80 x 210 cm negra; Tipo: Puerta de 1 hoja: 80 x 210 cm negra
Proceso por fases - Fase de creación: Nueva construcción
Restricciones - Nivel: Nivel: 03.ES.CUBIERTA; Altura de antepecho: 0.25 m

# IfcDoor: Puerta de cristal abatible en muro cortina (2)
In: 01.AR.PLANTA BAJA ACAB.SUELO
Type - OperationType: SINGLE_SWING_LEFT; ParameterTakesPrecedence: no; Sizeable: no; Material: Metal - Aluminio, Vidrio
Type - Construcción - Función: Exterior
Type - Cotas - Desfase: 0.051 m
Type - Datos de identidad - Marca de tipo: 12; Nombre de tipo: Puerta de cristal abatible en muro cortina
Type - Materiales y acabados - Material de cristalera: Vidrio
Type - Otros - Categoría: Puertas; Nombre de familia: Puerta de cristal abatible en muro cortina
Type - Propiedades analíticas - Coeficiente de incremento de calor solar: 0.86; Coeficiente de transferencia de calor (U): 5.5617; Construcción analítica: Ventanas grandes con acristalamiento simple; Resistencia térmica (R): 0.179801; Transmitancia de luz visual: 0.9
Type - Puerta de cristal abatible en muro cortina:Puerta de cristal abatible en muro cortina:200434 - PanelOperation: SWINGING
OverallHeight: 2.175 m; OverallWidth: 1.5 m
Cotas - Altura: 2.175 m; Anchura: 1.5 m; Área: 3.2625 m2; Volumen: 0.0420237 m3
Otros - ID de anfitrión: Muro cortina: Muro cortina - simple; Familia: Puerta de cristal abatible en muro cortina: Puerta de cristal abatible en muro cortina; Familia y tipo: Puerta de cristal abatible en muro cortina: Puerta de cristal abatible en muro cortina; ID de tipo: Puerta de cristal abatible en muro cortina: Puerta de cristal abatible en muro cortina; Tipo: Puerta de cristal abatible en muro cortina: Puerta de cristal abatible en muro cortina
Proceso por fases - Fase de creación: Nueva construcción
Restricciones - Nivel: Nivel: 01.AR.PLANTA BAJA ACAB.SUELO
Pset_DoorCommon - IsExternal: yes; Reference: Puerta de cristal abatible en muro cortina; ThermalTransmittance: 5.5617 kg/K/s3
Name (Puerta de cristal abatible en muro cortina:Puerta de cristal abatible en muro cortina:...)
200434
200208

# IfcDoor: Puerta de cristal abatible en muro cortina, Puerta de cristal abatible en muro cortina:Puerta de cristal abatible en muro cortina:200593
In: 01.AR.PLANTA BAJA ACAB.SUELO
Type - OperationType: SINGLE_SWING_LEFT; ParameterTakesPrecedence: no; Sizeable: no; Material: Metal - Aluminio, Vidrio
Type - Puerta de cristal abatible en muro cortina:Puerta de cristal abatible en muro cortina:200593 - PanelOperation: SWINGING
Type - Construcción - Función: Exterior
Type - Cotas - Desfase: 0.051 m
Type - Datos de identidad - Marca de tipo: 12; Nombre de tipo: Puerta de cristal abatible en muro cortina
Type - Materiales y acabados - Material de cristalera: Vidrio
Type - Otros - Categoría: Puertas; Nombre de familia: Puerta de cristal abatible en muro cortina
Type - Propiedades analíticas - Coeficiente de incremento de calor solar: 0.86; Coeficiente de transferencia de calor (U): 5.5617; Construcción analítica: Ventanas grandes con acristalamiento simple; Resistencia térmica (R): 0.179801; Transmitancia de luz visual: 0.9
OverallHeight: 2.275 m; OverallWidth: 1.5 m
Cotas - Altura: 2.275 m; Anchura: 1.5 m; Área: 3.4125 m2; Volumen: 0.0439287 m3
Otros - ID de anfitrión: Muro cortina: Muro cortina - simple; Familia: Puerta de cristal abatible en muro cortina: Puerta de cristal abatible en muro cortina; Familia y tipo: Puerta de cristal abatible en muro cortina: Puerta de cristal abatible en muro cortina; ID de tipo: Puerta de cristal abatible en muro cortina: Puerta de cristal abatible en muro cortina; Tipo: Puerta de cristal abatible en muro cortina: Puerta de cristal abatible en muro cortina
Proceso por fases - Fase de creación: Nueva construcción
Restricciones - Nivel: Nivel: 01.AR.PLANTA BAJA ACAB.SUELO
Pset_DoorCommon - IsExternal: yes; Reference: Puerta de cristal abatible en muro cortina; ThermalTransmittance: 5.5617 kg/K/s3

# IfcMember: Muro cortina:Muro cortina - simple:16523 (50)
In: 01.AR.PLANTA BAJA ACAB.SUELO
Otros - ID de anfitrión: Muro cortina: Muro cortina - simple; Categoría: Montantes de muro cortina; Familia: Montante rectangular: Montante rectangular - 5 x 10 cm; Familia y tipo: Montante rectangular: Montante rectangular - 5 x 10 cm; ID de tipo: Montante rectangular: Montante rectangular - 5 x 10 cm; Tipo: Montante rectangular: Montante rectangular - 5 x 10 cm; Nombre de familia: Montante rectangular
Proceso por fases - Fase de creación: Nueva construcción
Restricciones - Nivel: Nivel: 01.AR.PLANTA BAJA ACAB.SUELO; Desfase: 0 m; Ángulo: 0 deg
Pset_MemberCommon - LoadBearing: yes; IsExternal: yes; Reference: Montante rectangular - 5 x 10 cm
Construcción - Grosor: 0.1 m; Montante angular: no; Perfil: Perfil montante de muro cortina: 5 x 10 cm; Posición: Perpendicular a cara
Cotas - Anchura en lado 1: 0.025 m; Anchura en lado 2: 0.025 m
Datos de identidad - Nombre de tipo: Montante rectangular - 5 x 10 cm
Name (Muro cortina:Muro cortina - simple:...) | Área (m2) | Longitud (m) = Span (m) | Volumen (m3)
4 x 16523 | 0.455 | 3 | 0.015
4 x 16523 | 0.4775 | 3.15 | 0.01575
4 x 16523 | 0.11 | 0.7 | 0.0035
2 x 16523 | 0.19475 | 1.265 | 0.006325
4 x 16523 | 0.35 | 2.3 | 0.0115
2 x 16523 | 0.196259 | 1.27506 | 0.00637531
6 x 16523 | 0.23 | 1.5 | 0.0075
8 x 16523 | 0.125 | 0.8 | 0.004
2 x 16523 | 0.11675 | 0.745 | 0.003725
8 x 16523 | 0.335 | 2.2 | 0.011
2 x 16523 | 0.127241 | 0.814939 | 0.00407469
2 x 16523 | 0.19175 | 1.245 | 0.006225
2 x 16523 | 0.20075 | 1.305 | 0.006525

# IfcPlate: Acristalado (11)
In: 01.AR.PLANTA BAJA ACAB.SUELO
Type - ElementType: Acristalado; PredefinedType: CURTAIN_PANEL; Material: Cristal
Type - Cotas - Grosor: 0.02 m
Type - Datos de identidad - Nombre de tipo: Acristalado
Type - Materiales y acabados - Material: Cristal
Type - Otros - Categoría: Paneles de muro cortina; Nombre de familia: Panel de sistema
Type - Propiedades analíticas - Coeficiente de incremento de calor solar: 0.86; Coeficiente de transferencia de calor (U): 6.7069; Construcción analítica: 1/8 en cristalera simple Pilkington; Resistencia térmica (R): 0.1491; Transmitancia de luz visual: 0.9
Type - Restricciones - Desfase: 0 m
Otros - Familia: Panel de sistema: Acristalado; Familia y tipo: Panel de sistema: Acristalado; ID de anfitrión: Muro cortina: Muro cortina - simple; ID de tipo: Panel de sistema: Acristalado; Tipo: Panel de sistema: Acristalado
Proceso por fases - Fase de creación: Nueva construcción
Restricciones - Nivel: Nivel: 01.AR.PLANTA BAJA ACAB.SUELO
Pset_PlateCommon - LoadBearing: yes; IsExternal: yes; Reference: Acristalado; ThermalTransmittance: 6.7069 kg/K/s3
Name (Panel de sistema:Acristalado:...) | Altura (m) | Anchura (m) | Área (m2) | Volumen (m3)
193463 | 2.9 | 3.15 | 9.135 | 0.1827
193902 | 2.9 | 1.27506 | 3.69768 | 0.0739535
200544 | 2.9 | 1.265 | 3.6685 | 0.07337
201512 | 0.625 | 1.5 | 0.9375 | 0.01875 | Datos de identidad - Marca: 26
194047 | 2.9 | 0.814939 | 2.36332 | 0.0472665
200299 | 2.9 | 0.745 | 2.1605 | 0.04321
201430 | 0.725 | 1.5 | 1.0875 | 0.02175 | Datos de identidad - Marca: 25
194192 | 2.9 | 1.305 | 3.7845 | 0.07569
200097 | 2.9 | 1.245 | 3.6105 | 0.07221
201345 | 0.725 | 1.5 | 1.0875 | 0.02175 | Datos de identidad - Marca: 24
194257 | 2.9 | 3.15 | 9.135 | 0.1827

# IfcRoof: Cubierta básica:Plana invertida transitable tipo 2, Cubierta básica:Plana invertida transitable tipo 2:193097
In: 03.ES.CUBIERTA
Pset_RoofCommon - IsExternal: yes; Reference: Plana invertida transitable tipo 2; TotalArea: 41.7075 m2; ProjectedArea: 41.7075 m2
Construcción - Corte de alero: Corte a plomo; Profundidad de imposta: 0 m; Altura de cumbrera máxima: 3.47 m; Grosor predeterminado: 0.02 m
Cotas - Área: 41.7075 m2; Grosor: 0.02 m; Volumen: 0.83415 m3
Otros - Categoría: Cubiertas; Familia: Cubierta básica: Plana invertida transitable tipo 2; Familia y tipo: Cubierta básica: Plana invertida transitable tipo 2; ID de tipo: Cubierta básica: Plana invertida transitable tipo 2; Tipo: Cubierta básica: Plana invertida transitable tipo 2; Nombre de familia: Cubierta básica
Proceso por fases - Fase de creación: Nueva construcción
Restricciones - Delimitación de habitación: yes; Relacionado con masa: no; Desfase del límite: 0 m; Nivel base: Nivel: 03.ES.CUBIERTA; Desfase base desde nivel: -3.33 m
Datos de identidad - Nombre de tipo: Plana invertida transitable tipo 2
Gráficos - Color de relleno de detalle bajo: 0
Propiedades analíticas - Aspereza: 3; Absortancia: 0.7

# IfcRoof: Cubierta básica:Plana invertida transitable:82510, Cubierta básica:Plana invertida transitable:191978
In: 03.ES.CUBIERTA
Pset_RoofCommon - IsExternal: yes; Reference: Plana invertida transitable; TotalArea: 119.579 m2; ProjectedArea: 131.314 m2
Construcción - Altura de cumbrera máxima: 7.03 m; Corte de alero: Corte a plomo; Profundidad de imposta: 0 m; Grosor predeterminado: 0.25 m
Cotas - Área: 119.579 m2; Grosor: 0.25 m; Volumen: 29.8949 m3
Otros - Categoría: Cubiertas; Familia: Cubierta básica: Plana invertida transitable; Familia y tipo: Cubierta básica: Plana invertida transitable; ID de tipo: Cubierta básica: Plana invertida transitable; Tipo: Cubierta básica: Plana invertida transitable; Nombre de familia: Cubierta básica
Proceso por fases - Fase de creación: Nueva construcción
Restricciones - Delimitación de habitación: yes; Relacionado con masa: no; Desfase base desde nivel: 0 m; Desfase del límite: 0 m; Nivel base: Nivel: 03.ES.CUBIERTA
Datos de identidad - Nombre de tipo: Plana invertida transitable
Gráficos - Color de relleno de detalle bajo: 0
Propiedades analíticas - Aspereza: 3; Absortancia: 0.7

# IfcSlab: Cubierta básica:Plana invertida transitable tipo 2, Cubierta básica:Plana invertida transitable tipo 2:193097
In: 03.ES.CUBIERTA
PredefinedType: ROOF; Material: Azulejos de cerámica 0.01 m, Mortero de hormigón 0.01 m
Pset_SlabCommon - LoadBearing: yes; IsExternal: yes; PitchAngle: 0 deg; Reference: Plana invertida transitable tipo 2

# IfcSlab: Cubierta básica:Plana invertida transitable:82510, Cubierta básica:Plana invertida transitable:191978:1
In: 03.ES.CUBIERTA
PredefinedType: ROOF; Material: Azulejos de cerámica 0.01 m, Mortero de hormigón 0.01 m, Mortero de hormigón 0.04 m, Aislamiento - Paneles 0.05 m, Mortero de hormigón 0.04 m, Cubiertas - Arcilla seca expandida 0.1 m; Cubiertas - Arcilla seca expandida
Pset_SlabCommon - LoadBearing: yes; IsExternal: yes; PitchAngle: 0 deg; Reference: Plana invertida transitable

# IfcSlab: Losa Escalera 2:Losa Escalera 2, Losa Escalera 2:Losa Escalera 2:164334
In: 01.AR.PLANTA BAJA ACAB.SUELO
PredefinedType: FLOOR; Material: Suelos por defecto
Pset_SlabCommon - IsExternal: no; LoadBearing: yes; Reference: Losa Escalera 2
Cotas - Área: 0.608778 m2; Volumen: 0.112746 m3
Otros - Categoría: Suelos; Familia: Losa Escalera 2: Losa Escalera 2; Familia y tipo: Losa Escalera 2: Losa Escalera 2; ID de tipo: Losa Escalera 2: Losa Escalera 2; Tipo: Losa Escalera 2: Losa Escalera 2; Nombre de familia: Losa Escalera 2
Proceso por fases - Fase de creación: Nueva construcción
Restricciones - Delimitación de habitación: yes; Alzado: 0 m; Se mueve con elementos cercanos: no; Nivel: Nivel: 01.AR.PLANTA BAJA ACAB.SUELO
Datos de identidad - Nombre de tipo: Losa Escalera 2

# IfcSlab: Losa Escalera 3:Losa Escalera 2, Losa Escalera 3:Losa Escalera 2:169424
In: 02.ES.PLANTA PRIMERA
PredefinedType: FLOOR; Material: Suelos por defecto
Pset_SlabCommon - IsExternal: no; LoadBearing: yes; Reference: Losa Escalera 2
Cotas - Área: 0.608778 m2; Volumen: 0.11424 m3
Otros - Categoría: Suelos; Familia: Losa Escalera 3: Losa Escalera 2; Familia y tipo: Losa Escalera 3: Losa Escalera 2; ID de tipo: Losa Escalera 3: Losa Escalera 2; Tipo: Losa Escalera 3: Losa Escalera 2; Nombre de familia: Losa Escalera 3
Proceso por fases - Fase de creación: Nueva construcción
Restricciones - Delimitación de habitación: yes; Nivel: Nivel: 02.ES.PLANTA PRIMERA; Se mueve con elementos cercanos: no; Alzado: -0.662534 m
Datos de identidad - Nombre de tipo: Losa Escalera 2

# IfcSlab: Losa escalera:Losa escalera, Losa escalera:Losa escalera:163600
In: 01.AR.PLANTA BAJA ACAB.SUELO
PredefinedType: FLOOR; Material: Suelos por defecto
Pset_SlabCommon - IsExternal: no; LoadBearing: yes; Reference: Losa escalera
Cotas - Área: 0.544847 m2; Volumen: 0.558468 m3
Otros - Categoría: Suelos; Familia: Losa escalera: Losa escalera; Familia y tipo: Losa escalera: Losa escalera; ID de tipo: Losa escalera: Losa escalera; Tipo: Losa escalera: Losa escalera; Nombre de familia: Losa escalera
Proceso por fases - Fase de creación: Nueva construcción
Restricciones - Delimitación de habitación: yes; Alzado: 0 m; Nivel: Nivel: 01.AR.PLANTA BAJA ACAB.SUELO; Se mueve con elementos cercanos: no
Datos de identidad - Nombre de tipo: Losa escalera

# IfcSlab: Peldaño 2:Peldaño 1, Peldaño 2:Peldaño 1:168479
In: 02.ES.PLANTA PRIMERA
PredefinedType: FLOOR; Material: Suelos por defecto
Pset_SlabCommon - IsExternal: no; LoadBearing: yes; Reference: Peldaño 1
Cotas - Área: 2.22092 m2; Volumen: 0.487458 m3
Otros - Categoría: Suelos; Familia: Peldaño 2: Peldaño 1; Familia y tipo: Peldaño 2: Peldaño 1; ID de tipo: Peldaño 2: Peldaño 1; Tipo: Peldaño 2: Peldaño 1; Nombre de familia: Peldaño 2
Proceso por fases - Fase de creación: Nueva construcción
Restricciones - Delimitación de habitación: yes; Nivel: Nivel: 02.ES.PLANTA PRIMERA; Se mueve con elementos cercanos: no
Datos de identidad - Nombre de tipo: Peldaño 1

# IfcSlab: Peldaño 3:Peldaño 1, Peldaño 3:Peldaño 1:168883
In: 03.ES.CUBIERTA
PredefinedType: FLOOR; Material: Suelos por defecto
Pset_SlabCommon - IsExternal: no; LoadBearing: yes; Reference: Peldaño 1
Cotas - Área: 2.22092 m2; Volumen: 0.487458 m3
Otros - Categoría: Suelos; Familia: Peldaño 3: Peldaño 1; Familia y tipo: Peldaño 3: Peldaño 1; ID de tipo: Peldaño 3: Peldaño 1; Tipo: Peldaño 3: Peldaño 1; Nombre de familia: Peldaño 3
Proceso por fases - Fase de creación: Nueva construcción
Restricciones - Delimitación de habitación: yes; Nivel: Nivel: 03.ES.CUBIERTA; Alzado: 0 m; Se mueve con elementos cercanos: no
Datos de identidad - Nombre de tipo: Peldaño 1

# IfcSlab: Suelo:Acabado de suelo gres (4)
PredefinedType: FLOOR; Material: Baldosa Cerámica 0.015 m, Hormigón 0.065 m
Pset_SlabCommon - IsExternal: no; LoadBearing: yes; Reference: Acabado de suelo gres; ThermalTransmittance: 12.3622 kg/K/s3
Cotas - Grosor: 0.08 m
Estructura - Activar modelo analítico: no; Estructura: no
Otros - Categoría: Suelos; Familia: Suelo: Acabado de suelo gres; Familia y tipo: Suelo: Acabado de suelo gres; ID de tipo: Suelo: Acabado de suelo gres; Tipo: Suelo: Acabado de suelo gres; Nombre de familia: Suelo
Proceso por fases - Fase de creación: Nueva construcción
Restricciones - Delimitación de habitación: yes; Relacionado con masa: no; Desfase de altura desde nivel: 0 m
Construcción - Función: Interior; Grosor predeterminado: 0.08 m
Datos de identidad - Nombre de tipo: Acabado de suelo gres; Nota clave: S.4.2
Gráficos - Color de relleno de detalle bajo: 0
Materiales y acabados - Material estructural: Hormigón
Propiedades analíticas - Aspereza: 3; Absortancia: 0.7; Coeficiente de transferencia de calor (U): 12.3622; Masa térmica: 119896; Resistencia térmica (R): 0.0808915
Name (Suelo:Acabado de suelo gres:...) | In | Área (m2) | Elevación en parte inferior (m) | Elevación en parte superior (m) | Perímetro (m) | Volumen (m3) | Nivel
171684 | 01.AR.PLANTA BAJA ACAB.SUELO | 25.3771 | 0.12 | 0.2 | 27.4461 | 2.03017 | Nivel: 01.AR.PLANTA BAJA ACAB.SUELO
171684:2 | 01.AR.PLANTA BAJA ACAB.SUELO | 25.3771 | 0.12 | 0.2 | 27.4461 | 2.03017 | Nivel: 01.AR.PLANTA BAJA ACAB.SUELO
174441 | 02.AR.PLANTA PRIMERA ACAB. SUELO | 14.9003 | 3.45 | 3.53 | 21.863 | 1.19203 | Nivel: 02.AR.PLANTA PRIMERA ACAB. SUELO
174441:2 | 02.AR.PLANTA PRIMERA ACAB. SUELO | 14.9003 | 3.45 | 3.53 | 21.863 | 1.19203 | Nivel: 02.AR.PLANTA PRIMERA ACAB. SUELO

# IfcSlab: Suelo:Acabado de suelo parquet (9)
PredefinedType: FLOOR; Material: Madera - Parquet 0.015 m, Hormigón 0.065 m
Pset_SlabCommon - IsExternal: no; LoadBearing: yes; Reference: Acabado de suelo parquet; ThermalTransmittance: 16.0923 kg/K/s3
Cotas - Grosor: 0.08 m
Estructura - Activar modelo analítico: no; Estructura: no
Otros - Categoría: Suelos; Familia: Suelo: Acabado de suelo parquet; Familia y tipo: Suelo: Acabado de suelo parquet; ID de tipo: Suelo: Acabado de suelo parquet; Tipo: Suelo: Acabado de suelo parquet; Nombre de familia: Suelo
Proceso por fases - Fase de creación: Nueva construcción
Restricciones - Delimitación de habitación: yes; Relacionado con masa: no; Desfase de altura desde nivel: 0 m
Construcción - Función: Interior; Grosor predeterminado: 0.08 m
Datos de identidad - Nombre de tipo: Acabado de suelo parquet; Nota clave: S.4.2
Gráficos - Color de relleno de detalle bajo: 0
Materiales y acabados - Material estructural: Hormigón
Propiedades analíticas - Aspereza: 3; Absortancia: 0.7; Coeficiente de transferencia de calor (U): 16.0923; Masa térmica: 98221.5; Resistencia térmica (R): 0.0621415
Name (Suelo:Acabado de suelo parquet:...) | In | Área (m2) | Elevación en parte inferior (m) | Elevación en parte superior (m) | Perímetro (m) | Volumen (m3) | Nivel
170473 | 01.AR.PLANTA BAJA ACAB.SUELO | 95.282 | 0.12 | 0.2 | 87.593 | 7.62256 | Nivel: 01.AR.PLANTA BAJA ACAB.SUELO
170473:2 | 01.AR.PLANTA BAJA ACAB.SUELO | 95.282 | 0.12 | 0.2 | 87.593 | 7.62256 | Nivel: 01.AR.PLANTA BAJA ACAB.SUELO
170473:3 | 01.AR.PLANTA BAJA ACAB.SUELO | 95.282 | 0.12 | 0.2 | 87.593 | 7.62256 | Nivel: 01.AR.PLANTA BAJA ACAB.SUELO
173345 | 02.AR.PLANTA PRIMERA ACAB. SUELO | 105.806 | 3.45 | 3.53 | 105.156 | 8.46448 | Nivel: 02.AR.PLANTA PRIMERA ACAB. SUELO
173345:2 | 02.AR.PLANTA PRIMERA ACAB. SUELO | 105.806 | 3.45 | 3.53 | 105.156 | 8.46448 | Nivel: 02.AR.PLANTA PRIMERA ACAB. SUELO
173345:3 | 02.AR.PLANTA PRIMERA ACAB. SUELO | 105.806 | 3.45 | 3.53 | 105.156 | 8.46448 | Nivel: 02.AR.PLANTA PRIMERA ACAB. SUELO
173345:4 | 02.AR.PLANTA PRIMERA ACAB. SUELO | 105.806 | 3.45 | 3.53 | 105.156 | 8.46448 | Nivel: 02.AR.PLANTA PRIMERA ACAB. SUELO
173345:5 | 02.AR.PLANTA PRIMERA ACAB. SUELO | 105.806 | 3.45 | 3.53 | 105.156 | 8.46448 | Nivel: 02.AR.PLANTA PRIMERA ACAB. SUELO
173345:6 | 02.AR.PLANTA PRIMERA ACAB. SUELO | 105.806 | 3.45 | 3.53 | 105.156 | 8.46448 | Nivel: 02.AR.PLANTA PRIMERA ACAB. SUELO

# IfcSlab: Suelo:Forjado bovedilla + vigueta - 25 cm (11)
PredefinedType: FLOOR; Material: Suelos por defecto 0.25 m
Pset_SlabCommon - IsExternal: no; LoadBearing: yes; Reference: Forjado bovedilla + vigueta - 25 cm; PitchAngle: 0 deg
Cotas - Grosor: 0.25 m
Estructura - Activar modelo analítico: no; Estructura: no
Otros - Categoría: Suelos; Familia: Suelo: Forjado bovedilla + vigueta - 25 cm; Familia y tipo: Suelo: Forjado bovedilla + vigueta - 25 cm; ID de tipo: Suelo: Forjado bovedilla + vigueta - 25 cm; Tipo: Suelo: Forjado bovedilla + vigueta - 25 cm; Nombre de familia: Suelo
Proceso por fases - Fase de creación: Nueva construcción
Restricciones - Delimitación de habitación: yes; Relacionado con masa: no; Desfase de altura desde nivel: 0 m
Construcción - Función: Interior; Grosor predeterminado: 0.25 m
Datos de identidad - Nombre de tipo: Forjado bovedilla + vigueta - 25 cm; Nota clave: S.6
Gráficos - Color de relleno de detalle bajo: 0
Propiedades analíticas - Aspereza: 3; Absortancia: 0.7
Name (Suelo:Forjado bovedilla + vigueta - 25 cm:...) | In | Área (m2) | Elevación en parte inferior (m) | Elevación en parte superior (m) | Perímetro (m) | Volumen (m3) | Nivel
154778 | 01.ES.FORJADO PLANTA BAJA | 177.083 | -0.13 | 0.12 | 53.43 | 44.2708 | Nivel: 01.ES.FORJADO PLANTA BAJA
156114 | 02.ES.PLANTA PRIMERA | 40.915 | 3.2 | 3.45 | 31.18 | 10.2288 | Nivel: 02.ES.PLANTA PRIMERA
156141 | 02.ES.PLANTA PRIMERA | 55.7375 | 3.2 | 3.45 | 33.6 | 13.9344 | Nivel: 02.ES.PLANTA PRIMERA
156169 | 02.ES.PLANTA PRIMERA | 12.793 | 3.2 | 3.45 | 16.03 | 3.19825 | Nivel: 02.ES.PLANTA PRIMERA
156197 | 02.ES.PLANTA PRIMERA | 8.954 | 3.2 | 3.45 | 12.54 | 2.2385 | Nivel: 02.ES.PLANTA PRIMERA
156225 | 02.ES.PLANTA PRIMERA | 43.4875 | 3.2 | 3.45 | 31.6 | 10.8719 | Nivel: 02.ES.PLANTA PRIMERA
157626 | 03.ES.CUBIERTA | 55.6237 | 6.53 | 6.78 | 33.55 | 13.9059 | Nivel: 03.ES.CUBIERTA
157654 | 03.ES.CUBIERTA | 10.285 | 6.53 | 6.78 | 13.75 | 2.57125 | Nivel: 03.ES.CUBIERTA
157682 | 03.ES.CUBIERTA | 43.4875 | 6.53 | 6.78 | 31.6 | 10.8719 | Nivel: 03.ES.CUBIERTA
157710 | 03.ES.CUBIERTA | 0.962 | 6.53 | 6.78 | 3.93 | 0.2405 | Nivel: 03.ES.CUBIERTA
157739 | 03.ES.CUBIERTA | 8.954 | 6.53 | 6.78 | 12.54 | 2.2385 | Nivel: 03.ES.CUBIERTA

# IfcSlab: Suelo:Por defecto - 30 cm, Suelo:Por defecto - 30 cm:192999
In: 03.ES.CUBIERTA
PredefinedType: FLOOR; Material: Suelos por defecto 0.3 m
Pset_SlabCommon - IsExternal: no; LoadBearing: yes; PitchAngle: 0 deg; Reference: Por defecto - 30 cm
Cotas - Área: 11.7345 m2; Elevación en parte inferior: 9.38 m; Elevación en parte superior: 9.68 m; Grosor: 0.3 m; Perímetro: 13.8112 m; Volumen: 3.52034 m3
Estructura - Activar modelo analítico: no; Estructura: no
Otros - Categoría: Suelos; Familia: Suelo: Por defecto - 30 cm; Familia y tipo: Suelo: Por defecto - 30 cm; ID de tipo: Suelo: Por defecto - 30 cm; Tipo: Suelo: Por defecto - 30 cm; Nombre de familia: Suelo
Proceso por fases - Fase de creación: Nueva construcción
Restricciones - Delimitación de habitación: yes; Relacionado con masa: no; Nivel: Nivel: 03.ES.CUBIERTA; Desfase de altura desde nivel: 2.9 m
Construcción - Función: Interior; Grosor predeterminado: 0.3 m
Datos de identidad - Nombre de tipo: Por defecto - 30 cm; Nota clave: S.6
Gráficos - Color de relleno de detalle bajo: 0
Propiedades analíticas - Aspereza: 3; Absortancia: 0.7
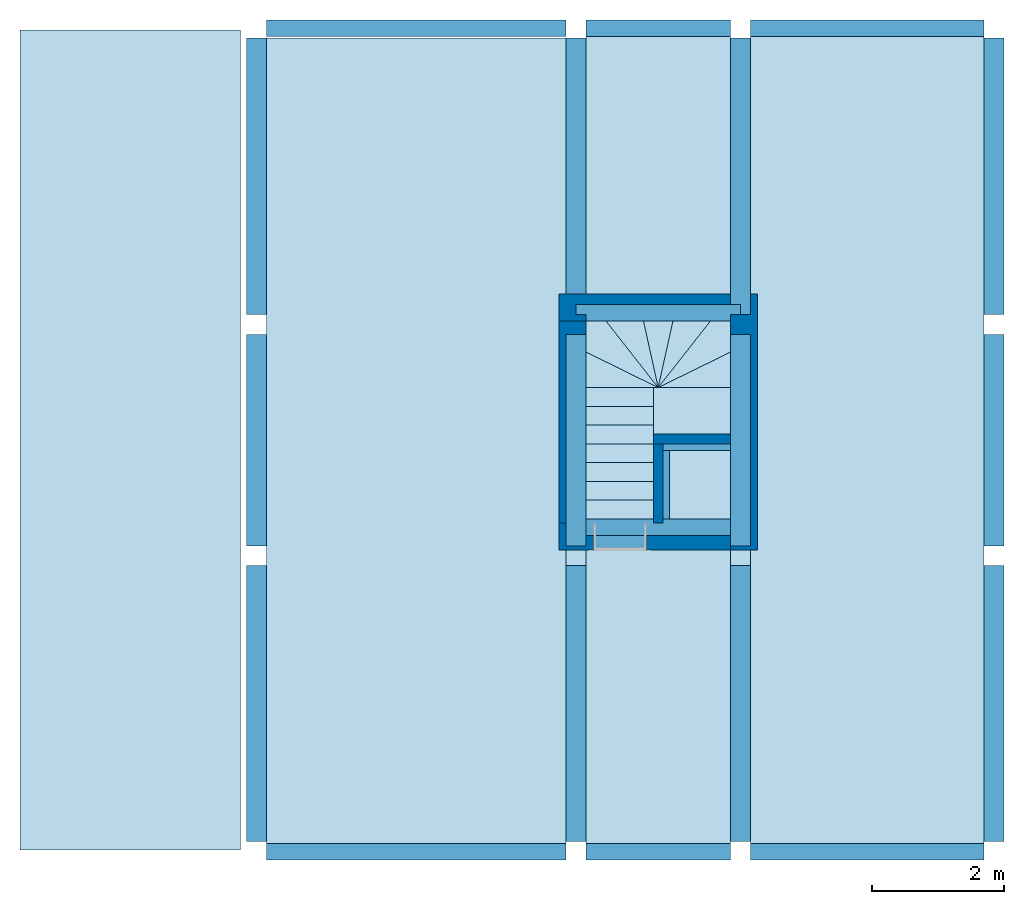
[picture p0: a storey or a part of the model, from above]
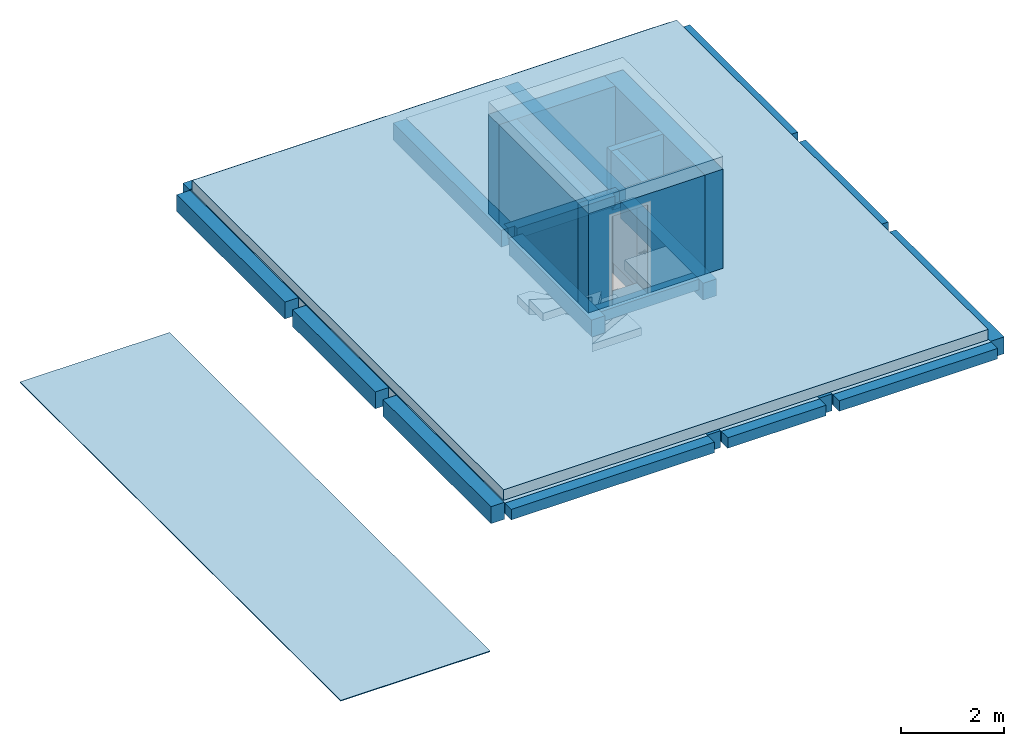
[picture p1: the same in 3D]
Properties of the parts of a building model (IFC2X3), part 2 of 2

# IfcSlab: Suelo:Solera - 8 cm, Suelo:Solera - 8 cm:193351
In: 01.ES.FORJADO PLANTA BAJA
PredefinedType: FLOOR; Material: Hormigón 0.08 m
Pset_SlabCommon - IsExternal: no; LoadBearing: yes; PitchAngle: 0 deg; Reference: Solera - 8 cm; ThermalTransmittance: 13.075 kg/K/s3
Cotas - Área: 45.12 m2; Elevación en parte inferior: 0.12 m; Elevación en parte superior: 0.2 m; Grosor: 0.08 m; Perímetro: 32.65 m; Volumen: 3.6096 m3
Estructura - Activar modelo analítico: no; Estructura: no
Otros - Categoría: Suelos; Familia: Suelo: Solera - 8 cm; Familia y tipo: Suelo: Solera - 8 cm; ID de tipo: Suelo: Solera - 8 cm; Tipo: Suelo: Solera - 8 cm; Nombre de familia: Suelo
Proceso por fases - Fase de creación: Nueva construcción
Restricciones - Delimitación de habitación: yes; Relacionado con masa: no; Desfase de altura desde nivel: 0.08 m; Nivel: Nivel: 01.ES.FORJADO PLANTA BAJA
Construcción - Función: Interior; Grosor predeterminado: 0.08 m
Datos de identidad - Nombre de tipo: Solera - 8 cm; Nota clave: S.4.2
Gráficos - Color de relleno de detalle bajo: 0
Materiales y acabados - Material estructural: Hormigón
Propiedades analíticas - Aspereza: 3; Absortancia: 0.7; Coeficiente de transferencia de calor (U): 13.075; Masa térmica: 120888; Resistencia térmica (R): 0.0764818

# IfcSlab: Zapata-Rectangular:1200 x 1200 x 1000 mm (4)
In: 00.ES.CIMENTACIÓN
PredefinedType: FLOOR; Material: Hormigón - Hormigón moldeado in situ
Pset_SlabCommon - IsExternal: no; LoadBearing: yes; Reference: 1200 x 1200 x 1000 mm
Cotas - Anchura: 1.2 m; Área: 1.44 m2; Elevación en parte inferior: -1.68 m; Elevación en parte superior: -0.68 m; Longitud: 1.2 m; Volumen: 1.44 m3; Grosor: 1 m
Estructura - Activar modelo analítico: yes; Recubrimiento de armadura - Cara inferior: Configuración de recubrimiento de armadura: Revestimiento de armadura 1; Recubrimiento de armadura - Cara superior: Configuración de recubrimiento de armadura: Revestimiento de armadura 1; Recubrimiento de armadura - Otras caras: Configuración de recubrimiento de armadura: Revestimiento de armadura 1
Materiales y acabados - Material estructural: Hormigón - Hormigón moldeado in situ
Otros - Categoría: Cimentación estructural; Familia: Zapata-Rectangular: 1200 x 1200 x 1000 mm; Familia y tipo: Zapata-Rectangular: 1200 x 1200 x 1000 mm; ID de tipo: Zapata-Rectangular: 1200 x 1200 x 1000 mm; Tipo: Zapata-Rectangular: 1200 x 1200 x 1000 mm; Nombre de familia: Zapata-Rectangular
Proceso por fases - Fase de creación: Nueva construcción
Restricciones - Desfase: 0 m; Nivel: Nivel: 00.ES.CIMENTACIÓN; Se mueve con rejillas: yes; Anfitrión: Nivel : 00.ES.CIMENTACIÓN
Datos de identidad - Nombre de tipo: 1200 x 1200 x 1000 mm
Name (Zapata-Rectangular:1200 x 1200 x 1000 mm:...)
151116
151118
151120
151122

# IfcSlab: Zapata-Rectangular:1500 x 1500 x 1000 mm (16)
In: 00.ES.CIMENTACIÓN
PredefinedType: FLOOR; Material: Hormigón - Hormigón moldeado in situ
Pset_SlabCommon - Reference: 1500 x 1500 x 1000 mm; IsExternal: no; LoadBearing: yes
Cotas - Anchura: 1.5 m; Área: 2.25 m2; Elevación en parte inferior: -1.68 m; Elevación en parte superior: -0.68 m; Longitud: 1.5 m; Volumen: 2.25 m3; Grosor: 1 m
Estructura - Activar modelo analítico: yes; Recubrimiento de armadura - Cara inferior: Configuración de recubrimiento de armadura: Revestimiento de armadura 1; Recubrimiento de armadura - Cara superior: Configuración de recubrimiento de armadura: Revestimiento de armadura 1; Recubrimiento de armadura - Otras caras: Configuración de recubrimiento de armadura: Revestimiento de armadura 1
Materiales y acabados - Material estructural: Hormigón - Hormigón moldeado in situ
Otros - Categoría: Cimentación estructural; Familia: Zapata-Rectangular: 1500 x 1500 x 1000 mm; Familia y tipo: Zapata-Rectangular: 1500 x 1500 x 1000 mm; ID de tipo: Zapata-Rectangular: 1500 x 1500 x 1000 mm; Tipo: Zapata-Rectangular: 1500 x 1500 x 1000 mm; Nombre de familia: Zapata-Rectangular
Proceso por fases - Fase de creación: Nueva construcción
Restricciones - Anfitrión: Nivel : 00.ES.CIMENTACIÓN; Desfase: 0 m; Nivel: Nivel: 00.ES.CIMENTACIÓN; Se mueve con rejillas: yes
Datos de identidad - Nombre de tipo: 1500 x 1500 x 1000 mm
Name (Zapata-Rectangular:1500 x 1500 x 1000 mm:...)
150960
150962
150964
150966
150968
150970
150972
150974
150976
150978
150980
150982
150984
150986
150988
150990

# IfcSlab: escalera tramo 1:escalera tramo 2, escalera tramo 1:escalera tramo 2:169379
In: 03.ES.CUBIERTA
PredefinedType: FLOOR; Material: Suelos por defecto
Pset_SlabCommon - IsExternal: no; LoadBearing: yes; Reference: escalera tramo 2
Cotas - Área: 0.554243 m2; Volumen: 0.568099 m3
Otros - Categoría: Suelos; Familia: escalera tramo 1: escalera tramo 2; Familia y tipo: escalera tramo 1: escalera tramo 2; ID de tipo: escalera tramo 1: escalera tramo 2; Tipo: escalera tramo 1: escalera tramo 2; Nombre de familia: escalera tramo 1
Proceso por fases - Fase de creación: Nueva construcción
Restricciones - Delimitación de habitación: yes; Alzado: 0 m; Se mueve con elementos cercanos: no; Nivel: Nivel: 03.ES.CUBIERTA
Datos de identidad - Nombre de tipo: escalera tramo 2

# IfcSlab: escalera tramo 2:escalera tramo 2, escalera tramo 2:escalera tramo 2:167240
In: 02.ES.PLANTA PRIMERA
PredefinedType: FLOOR; Material: Suelos por defecto
Pset_SlabCommon - IsExternal: no; LoadBearing: yes; Reference: escalera tramo 2
Cotas - Área: 0.220061 m2; Volumen: 0.225563 m3
Otros - Categoría: Suelos; Familia: escalera tramo 2: escalera tramo 2; Familia y tipo: escalera tramo 2: escalera tramo 2; ID de tipo: escalera tramo 2: escalera tramo 2; Tipo: escalera tramo 2: escalera tramo 2; Nombre de familia: escalera tramo 2
Proceso por fases - Fase de creación: Nueva construcción
Restricciones - Delimitación de habitación: yes; Nivel: Nivel: 02.ES.PLANTA PRIMERA; Alzado: 0 m; Se mueve con elementos cercanos: no
Datos de identidad - Nombre de tipo: escalera tramo 2

# IfcSlab: tramo escalera 3:tramo escalera 3, tramo escalera 3:tramo escalera 3:168196
In: 02.AR.PLANTA PRIMERA ACAB. SUELO
PredefinedType: FLOOR; Material: Suelos por defecto
Pset_SlabCommon - IsExternal: no; LoadBearing: yes; Reference: tramo escalera 3
Cotas - Área: 0.268564 m2; Volumen: 0.275278 m3
Otros - Categoría: Suelos; Familia: tramo escalera 3: tramo escalera 3; Familia y tipo: tramo escalera 3: tramo escalera 3; ID de tipo: tramo escalera 3: tramo escalera 3; Tipo: tramo escalera 3: tramo escalera 3; Nombre de familia: tramo escalera 3
Proceso por fases - Fase de creación: Nueva construcción
Restricciones - Delimitación de habitación: yes; Alzado: 0 m; Se mueve con elementos cercanos: no; Nivel: Nivel: 02.AR.PLANTA PRIMERA ACAB. SUELO
Datos de identidad - Nombre de tipo: tramo escalera 3

# IfcWall: Muro básico:F3.2 (3)
In: 01.ES.FORJADO PLANTA BAJA
Type - PredefinedType: STANDARD; Material: APL-Enfoscado de mortero de cemento de resistencia muy alta a la filtración (B3) 0.015 m, APL-Pared de obra de fabrica de ladrillo ceramico perforado, de e=11,5cm 0.115 m, APL-Camara de aire no ventilada 0.075 m, APL-Poliestireno expandido elastificado de e=0.037 0.12 m, APL-Tabique de obra de fabrica de ladrillo ceramico hueco doble, de e=7cm 0.07 m, APL-Guarnecido de yeso 0.015 m
Type - Construcción - Función: Exterior; Anchura: 0.41 m; Envolvente en extremos: Ninguno; Envolvente en inserciones: Sin envolvente
Type - Datos de identidad - Nombre de tipo: F3.2
Type - Gráficos - Color de relleno de detalle bajo: 0
Type - Materiales y acabados - Material estructural: APL-Pared de obra de fabrica de ladrillo ceramico perforado, de e=11,5cm
Type - Otros - Categoría: Muros; Nombre de familia: Muro básico
Type - Propiedades analíticas - Absortancia: 0.1; Aspereza: 1
Estructura - Activar modelo analítico: no; Estructura: no; Uso estructural: No portante
Otros - Familia: Muro básico: F3.2; Familia y tipo: Muro básico: F3.2; ID de tipo: Muro básico: F3.2; Tipo: Muro básico: F3.2
Proceso por fases - Fase de creación: Nueva construcción
Restricciones - Delimitación de habitación: yes; Desfase de base: 0 m; Distancia de extensión de base: 0 m; Distancia de extensión superior: 0 m; La base está enlazada: no; La parte superior está enlazada: no; Relacionado con masa: no; Línea de ubicación: Cara de acabado: Interior; Restricción de base: Nivel: 01.ES.FORJADO PLANTA BAJA; Restricción superior: Nivel: 03.ES.CUBIERTA; Altura desconectada: 7.61 m; Desfase superior: 0.95 m
Pset_WallCommon - LoadBearing: no; ExtendToStructure: no; IsExternal: yes; Reference: F3.2
Name (Muro básico:F3.2:...) | Área (m2) | Longitud (m) | Volumen (m3)
158723 | 73.2765 | 12.65 | 26.8321
158787 | 75.1247 | 11.27 | 28.3507
158837 | 76.6564 | 12.5015 | 29.1194

# IfcWall: Muro básico:Por defecto - 15 cm, Muro básico:Por defecto - 15 cm:159673
In: 01.ES.FORJADO PLANTA BAJA
Type - PredefinedType: STANDARD; Material: Muro por defecto 0.15 m
Type - Construcción - Función: Exterior; Envolvente en extremos: Ninguno; Envolvente en inserciones: Sin envolvente; Anchura: 0.15 m
Type - Datos de identidad - Nombre de tipo: Por defecto - 15 cm; Nota clave: Md.1
Type - Gráficos - Color de relleno de detalle bajo: 0
Type - Otros - Categoría: Muros; Nombre de familia: Muro básico
Type - Propiedades analíticas - Aspereza: 3; Absortancia: 0.7
Cotas - Área: 9.6406 m2; Longitud: 3.975 m; Volumen: 1.37767 m3
Estructura - Activar modelo analítico: no; Estructura: no; Uso estructural: No portante
Otros - Familia: Muro básico: Por defecto - 15 cm; Familia y tipo: Muro básico: Por defecto - 15 cm; ID de tipo: Muro básico: Por defecto - 15 cm; Tipo: Muro básico: Por defecto - 15 cm
Proceso por fases - Fase de creación: Nueva construcción
Restricciones - Delimitación de habitación: yes; Desfase de base: 0 m; Distancia de extensión de base: 0 m; Distancia de extensión superior: 0 m; La base está enlazada: no; La parte superior está enlazada: no; Relacionado con masa: no; Línea de ubicación: Cara de acabado: Interior; Restricción de base: Nivel: 01.ES.FORJADO PLANTA BAJA; Restricción superior: Nivel: 02.ES.PLANTA PRIMERA; Altura desconectada: 3.08 m; Desfase superior: -0.25 m
Pset_WallCommon - LoadBearing: no; ExtendToStructure: no; IsExternal: yes; Reference: Por defecto - 15 cm

# IfcWallStandardCase: Muro básico:F3.2 (5)
Type - PredefinedType: STANDARD; Material: APL-Enfoscado de mortero de cemento de resistencia muy alta a la filtración (B3) 0.015 m, APL-Pared de obra de fabrica de ladrillo ceramico perforado, de e=11,5cm 0.115 m, APL-Camara de aire no ventilada 0.075 m, APL-Poliestireno expandido elastificado de e=0.037 0.12 m, APL-Tabique de obra de fabrica de ladrillo ceramico hueco doble, de e=7cm 0.07 m, APL-Guarnecido de yeso 0.015 m
Type - Construcción - Función: Exterior; Anchura: 0.41 m; Envolvente en extremos: Ninguno; Envolvente en inserciones: Sin envolvente
Type - Datos de identidad - Nombre de tipo: F3.2
Type - Gráficos - Color de relleno de detalle bajo: 0
Type - Materiales y acabados - Material estructural: APL-Pared de obra de fabrica de ladrillo ceramico perforado, de e=11,5cm
Type - Otros - Categoría: Muros; Nombre de familia: Muro básico
Type - Propiedades analíticas - Absortancia: 0.1; Aspereza: 1
Estructura - Activar modelo analítico: no; Estructura: no; Uso estructural: No portante
Otros - Familia: Muro básico: F3.2; Familia y tipo: Muro básico: F3.2; ID de tipo: Muro básico: F3.2; Tipo: Muro básico: F3.2
Proceso por fases - Fase de creación: Nueva construcción
Restricciones - Delimitación de habitación: yes; Desfase de base: 0 m; Distancia de extensión de base: 0 m; Distancia de extensión superior: 0 m; La base está enlazada: no; La parte superior está enlazada: no; Relacionado con masa: no; Línea de ubicación: Cara de acabado: Interior
Pset_WallCommon - LoadBearing: no; ExtendToStructure: no; IsExternal: yes; Reference: F3.2
Name (Muro básico:F3.2:...) | In | Área (m2) | Longitud (m) | Volumen (m3) | Altura desconectada (m) | Desfase superior (m) | Restricción de base
158629 | 01.ES.FORJADO PLANTA BAJA | 76.1448 | 11.27 | 28.2183 | 7.61 | 0.95 | Nivel: 01.ES.FORJADO PLANTA BAJA | Restricciones - Restricción superior: Nivel: 03.ES.CUBIERTA
191662 | 03.ES.CUBIERTA | 6.786 | 2.61 | 2.78226 | 2.6 | 0.4 | Nivel: 03.ES.CUBIERTA
191686 | 03.ES.CUBIERTA | 10.1025 | 3.47559 | 4.14204 | 2.6 | 0.4 | Nivel: 03.ES.CUBIERTA
191815 | 03.ES.CUBIERTA | 5.106 | 2.61 | 2.09346 | 2.6 | 0.4 | Nivel: 03.ES.CUBIERTA
191868 | 03.ES.CUBIERTA | 7.97053 | 3.47559 | 3.26792 | 2.6 | 0.4 | Nivel: 03.ES.CUBIERTA

# IfcWallStandardCase: Muro básico:Hormigón - 30 cm (7)
In: 00.ES.CIMENTACIÓN
Type - PredefinedType: STANDARD; Material: Hormigón, Moldeado in situ, gris 0.3 m
Type - Construcción - Anchura: 0.3 m; Envolvente en extremos: Exterior; Envolvente en inserciones: Exterior; Función: Exterior
Type - Datos de identidad - Nombre de tipo: Hormigón - 30 cm; Nota clave: Me.1.1
Type - Gráficos - Color de relleno de detalle bajo: 0
Type - Materiales y acabados - Material estructural: Hormigón, Moldeado in situ, gris
Type - Otros - Categoría: Muros; Nombre de familia: Muro básico
Type - Propiedades analíticas - Absortancia: 0.7; Aspereza: 3; Coeficiente de transferencia de calor (U): 3.48667; Masa térmica: 453330; Resistencia térmica (R): 0.286807
Estructura - Activar modelo analítico: no; Estructura: no; Uso estructural: No portante
Otros - Familia: Muro básico: Hormigón - 30 cm; Familia y tipo: Muro básico: Hormigón - 30 cm; ID de tipo: Muro básico: Hormigón - 30 cm; Tipo: Muro básico: Hormigón - 30 cm
Proceso por fases - Fase de creación: Nueva construcción
Restricciones - Delimitación de habitación: yes; Desfase de base: 0 m; Desfase superior: 0 m; Distancia de extensión de base: 0 m; Distancia de extensión superior: 0 m; La base está enlazada: no; La parte superior está enlazada: no; Línea de ubicación: Eje del muro; Relacionado con masa: no; Restricción de base: Nivel: 00.ES.CIMENTACIÓN
Pset_WallCommon - Reference: Hormigón - 30 cm; LoadBearing: no; ExtendToStructure: no; IsExternal: yes; ThermalTransmittance: 3.48667 kg/K/s3
Name (Muro básico:Hormigón - 30 cm:...) | Área (m2) | Longitud (m) | Volumen (m3) | Altura desconectada (m)
152231 | 11.132 | 14.815 | 3.3396 | 0.8
152295 | 10 | 12.5 | 2.85 | 0.8
152370 | 10.892 | 14.815 | 3.2676 | 0.8
152454 | 9.28 | 12.5 | 2.784 | 0.8
152867 | 6.38 | 12.5 | 1.914 | 0.55
152952 | 6.38 | 12.5 | 1.914 | 0.55
152962 | 6.38 | 12.5 | 1.914 | 0.55

# IfcWallStandardCase: Muro básico:Por defecto - 15 cm (25)
Type - PredefinedType: STANDARD; Material: Muro por defecto 0.15 m
Type - Construcción - Función: Exterior; Envolvente en extremos: Ninguno; Envolvente en inserciones: Sin envolvente; Anchura: 0.15 m
Type - Datos de identidad - Nombre de tipo: Por defecto - 15 cm; Nota clave: Md.1
Type - Gráficos - Color de relleno de detalle bajo: 0
Type - Otros - Categoría: Muros; Nombre de familia: Muro básico
Type - Propiedades analíticas - Aspereza: 3; Absortancia: 0.7
Estructura - Activar modelo analítico: no; Estructura: no; Uso estructural: No portante
Otros - Familia: Muro básico: Por defecto - 15 cm; Familia y tipo: Muro básico: Por defecto - 15 cm; ID de tipo: Muro básico: Por defecto - 15 cm; Tipo: Muro básico: Por defecto - 15 cm
Proceso por fases - Fase de creación: Nueva construcción
Restricciones - Delimitación de habitación: yes; Distancia de extensión de base: 0 m; Distancia de extensión superior: 0 m; La base está enlazada: no; La parte superior está enlazada: no; Relacionado con masa: no; Línea de ubicación: Cara de acabado: Interior
Pset_WallCommon - LoadBearing: no; ExtendToStructure: no; IsExternal: yes; Reference: Por defecto - 15 cm
Name (Muro básico:Por defecto - 15 cm:...) | In | Área (m2) | Longitud (m) | Volumen (m3) | Altura desconectada (m) | Desfase de base (m) | Desfase superior (m) | Restricción de base | Restricción superior
159381 | 01.AR.PLANTA BAJA ACAB.SUELO | 34.0335 | 12.5015 | 4.62284 | 3.08 | -0.08 | -0.25 | Nivel: 01.AR.PLANTA BAJA ACAB.SUELO | Nivel: 02.ES.PLANTA PRIMERA
159520 | 01.ES.FORJADO PLANTA BAJA | 34.0335 | 12.5015 | 4.62284 | 3.08 | 0 | -0.25 | Nivel: 01.ES.FORJADO PLANTA BAJA | Nivel: 02.ES.PLANTA PRIMERA
159573 | 01.ES.FORJADO PLANTA BAJA | 5.2136 | 2.32 | 0.78204 | 3.08 | 0 | -0.25 | Nivel: 01.ES.FORJADO PLANTA BAJA | Nivel: 02.ES.PLANTA PRIMERA
159874 | 01.ES.FORJADO PLANTA BAJA | 5.0036 | 2.32 | 0.75054 | 3.08 | 0 | -0.25 | Nivel: 01.ES.FORJADO PLANTA BAJA | Nivel: 02.ES.PLANTA PRIMERA
169843 | 01.ES.FORJADO PLANTA BAJA | 1.8928 | 1.2 | 0.28392 | 3.08 | 0 | -0.25 | Nivel: 01.ES.FORJADO PLANTA BAJA | Nivel: 02.ES.PLANTA PRIMERA
169884 | 01.ES.FORJADO PLANTA BAJA | 3.21572 | 1.11907 | 0.482358 | 3.08 | 0 | -0.25 | Nivel: 01.ES.FORJADO PLANTA BAJA | Nivel: 02.ES.PLANTA PRIMERA
169922 | 02.ES.PLANTA PRIMERA | 4.12484 | 2.05566 | 0.618725 | 3.58 | -0.25 | 0 | Nivel: 02.ES.PLANTA PRIMERA | Nivel: 03.ES.CUBIERTA
172007 | 02.ES.PLANTA PRIMERA | 16.2917 | 6.89239 | 2.44376 | 3.08 | 0 | -0.25 | Nivel: 02.ES.PLANTA PRIMERA | Nivel: 03.ES.CUBIERTA
172097 | 02.ES.PLANTA PRIMERA | 5.306 | 2.35 | 0.7959 | 3.08 | 0 | -0.25 | Nivel: 02.ES.PLANTA PRIMERA | Nivel: 03.ES.CUBIERTA
172154 | 02.ES.PLANTA PRIMERA | 11.3321 | 4.38152 | 1.69981 | 3.08 | 0 | -0.25 | Nivel: 02.ES.PLANTA PRIMERA | Nivel: 03.ES.CUBIERTA
172239 | 02.ES.PLANTA PRIMERA | 9.1924 | 3.735 | 1.37886 | 3.08 | 0 | -0.25 | Nivel: 02.ES.PLANTA PRIMERA | Nivel: 03.ES.CUBIERTA
172356 | 02.ES.PLANTA PRIMERA | 30.0888 | 11.27 | 4.26384 | 3.08 | 0 | -0.25 | Nivel: 02.ES.PLANTA PRIMERA | Nivel: 03.ES.CUBIERTA
172461 | 02.ES.PLANTA PRIMERA | 12.7052 | 4.33006 | 1.90578 | 3.08 | 0 | -0.25 | Nivel: 02.ES.PLANTA PRIMERA | Nivel: 03.ES.CUBIERTA
172845 | 02.ES.PLANTA PRIMERA | 7.154 | 2.8 | 1.0731 | 3.08 | 0 | -0.25 | Nivel: 02.ES.PLANTA PRIMERA | Nivel: 03.ES.CUBIERTA
172890 | 02.ES.PLANTA PRIMERA | 10.4104 | 3.66 | 1.56156 | 3.08 | 0 | -0.25 | Nivel: 02.ES.PLANTA PRIMERA | Nivel: 03.ES.CUBIERTA
172979 | 02.ES.PLANTA PRIMERA | 1.8395 | 1.3 | 0.275925 | 3.08 | 0 | -0.25 | Nivel: 02.ES.PLANTA PRIMERA | Nivel: 03.ES.CUBIERTA
173090 | 01.ES.FORJADO PLANTA BAJA | 6.6836 | 2.32 | 1.00254 | 3.08 | 0 | -0.25 | Nivel: 01.ES.FORJADO PLANTA BAJA | Nivel: 02.ES.PLANTA PRIMERA
173148 | 02.ES.PLANTA PRIMERA | 6.776 | 2.35 | 1.0164 | 3.08 | 0 | -0.25 | Nivel: 02.ES.PLANTA PRIMERA | Nivel: 03.ES.CUBIERTA
173270 | 02.ES.PLANTA PRIMERA | 5.5963 | 1.91 | 0.839445 | 3.08 | 0 | -0.25 | Nivel: 02.ES.PLANTA PRIMERA | Nivel: 03.ES.CUBIERTA
181068 | 02.AR.PLANTA PRIMERA ACAB. SUELO | 1.20537 | 1.175 | 0.180806 | 2.815 | 0.185 | -0.25 | Nivel: 02.AR.PLANTA PRIMERA ACAB. SUELO | Nivel: 03.ES.CUBIERTA
192817 | 03.ES.CUBIERTA | 3.055 | 1.305 | 0.45825 | 2.6 | 0 | 0 | Nivel: 03.ES.CUBIERTA
192865 | 03.ES.CUBIERTA | 3.12413 | 1.48159 | 0.46862 | 2.6 | 0 | 0 | Nivel: 03.ES.CUBIERTA
193235 | 02.ES.PLANTA PRIMERA | 4.2 | 3.63 | 0.63 | 1.2 | 0 | 0 | Nivel: 02.ES.PLANTA PRIMERA
193287 | 02.ES.PLANTA PRIMERA | 15.12 | 12.6 | 2.268 | 1.2 | 0 | 0 | Nivel: 02.ES.PLANTA PRIMERA
193320 | 02.ES.PLANTA PRIMERA | 4.02 | 3.63 | 0.603 | 1.2 | 0 | 0 | Nivel: 02.ES.PLANTA PRIMERA

# IfcWallStandardCase: Muro básico:Por defecto - 7 cm, Muro básico:Por defecto - 7 cm:170195
In: 01.ES.FORJADO PLANTA BAJA
Type - PredefinedType: STANDARD; Material: Muro por defecto 0.07 m
Type - Construcción - Función: Exterior; Envolvente en extremos: Ninguno; Envolvente en inserciones: Sin envolvente; Anchura: 0.07 m
Type - Datos de identidad - Nombre de tipo: Por defecto - 7 cm; Nota clave: Md.1
Type - Gráficos - Color de relleno de detalle bajo: 0
Type - Otros - Categoría: Muros; Nombre de familia: Muro básico
Type - Propiedades analíticas - Aspereza: 3; Absortancia: 0.7
Cotas - Área: 2.46362 m2; Longitud: 0.874875 m; Volumen: 0.172453 m3
Estructura - Activar modelo analítico: no; Estructura: no; Uso estructural: No portante
Otros - Familia: Muro básico: Por defecto - 7 cm; Familia y tipo: Muro básico: Por defecto - 7 cm; ID de tipo: Muro básico: Por defecto - 7 cm; Tipo: Muro básico: Por defecto - 7 cm
Proceso por fases - Fase de creación: Nueva construcción
Restricciones - Delimitación de habitación: yes; Desfase de base: 0 m; Distancia de extensión de base: 0 m; Distancia de extensión superior: 0 m; La base está enlazada: no; La parte superior está enlazada: no; Relacionado con masa: no; Línea de ubicación: Cara de acabado: Interior; Restricción de base: Nivel: 01.ES.FORJADO PLANTA BAJA; Restricción superior: Nivel: 02.ES.PLANTA PRIMERA; Altura desconectada: 3.08 m; Desfase superior: -0.25 m
Pset_WallCommon - LoadBearing: no; ExtendToStructure: no; IsExternal: yes; Reference: Por defecto - 7 cm

# IfcWindow: VE1_100 x 140 cm (3)
Type - ParameterTakesPrecedence: no; Sizeable: no; Material: negro, Vidrio, Dark Oak
Type - Construcción - Cierre de muro: Por anfitrión
Type - Cotas - Altura: 1.4 m; Anchura: 1 m
Type - Datos de identidad - Imagen de tipo: Imagen ráster: W 632.jpg; Descripción: 60 mm, 3 sistemas del perfil de la cámara Apoyo de la PCR Soportar todas las condiciones climáticas Max Heat - aislamiento acústico y agua Con la PCR, no hay necesidad adicional de la zona de metal de refuerzo 32 mm de acristalamiento Desplazamiento Tipo de guillotina Canal de drenaje de agua Gama de colores laminada Su calidad está acreditada por certificado internacional; Marca de tipo: 21; Nombre de tipo: VE1_100 x 140 cm; Número OmniClass: 23.30.20.00; Título OmniClass: Windows
Type - Otros - Categoría: Ventanas; Altura de antepecho por defecto: 0.8 m; Nombre de familia: Ventana 1 hoja
Type - Propiedades analíticas - Construcción analítica: <Ninguno>
OverallHeight: 1.4 m; OverallWidth: 1 m
Pset_WindowCommon - IsExternal: yes; Reference: VE1_100 x 140 cm
Cotas - Altura superior: 2.2 m; Área: 2.11123 m2; Volumen: 0.0878161 m3
Otros - ID de anfitrión: Muro básico: F3.2; Altura de extremo inicial: 2.2 m; Familia: Ventana 1 hoja: VE1_100 x 140 cm; Familia y tipo: Ventana 1 hoja: VE1_100 x 140 cm; ID de tipo: Ventana 1 hoja: VE1_100 x 140 cm; Tipo: Ventana 1 hoja: VE1_100 x 140 cm
Proceso por fases - Fase de creación: Nueva construcción
Restricciones - Altura de antepecho: 0.8 m
Name (Ventana 1 hoja:VE1_100 x 140 cm:...) | In | Marca | Nivel
190435 | 02.AR.PLANTA PRIMERA ACAB. SUELO | 17 | Nivel: 02.AR.PLANTA PRIMERA ACAB. SUELO
190469 | 02.AR.PLANTA PRIMERA ACAB. SUELO | 18 | Nivel: 02.AR.PLANTA PRIMERA ACAB. SUELO
191324 | 01.AR.PLANTA BAJA ACAB.SUELO | 19 | Nivel: 01.AR.PLANTA BAJA ACAB.SUELO

# IfcWindow: VE1_140 x 140 cm (9)
Type - ParameterTakesPrecedence: no; Sizeable: no; Material: negro, Vidrio, Dark Oak
Type - Construcción - Cierre de muro: Por anfitrión
Type - Cotas - Altura: 1.4 m; Anchura: 1.4 m
Type - Datos de identidad - Descripción: 60 mm, 3 sistemas del perfil de la cámara Apoyo de la PCR Soportar todas las condiciones climáticas Max Heat - aislamiento acústico y agua Con la PCR, no hay necesidad adicional de la zona de metal de refuerzo 32 mm de acristalamiento Desplazamiento Tipo de guillotina Canal de drenaje de agua Gama de colores laminada Su calidad está acreditada por certificado internacional; Imagen de tipo: Imagen ráster: W 632.jpg; Marca de tipo: 19; Nombre de tipo: VE1_140 x 140 cm; Número OmniClass: 23.30.20.00; Título OmniClass: Windows
Type - Otros - Categoría: Ventanas; Altura de antepecho por defecto: 0.8 m; Nombre de familia: Ventana 1 hoja
Type - Propiedades analíticas - Construcción analítica: <Ninguno>
OverallHeight: 1.4 m; OverallWidth: 1.4 m
Pset_WindowCommon - IsExternal: yes; Reference: VE1_140 x 140 cm
Cotas - Altura superior: 2.2 m; Área: 2.84862 m2; Volumen: 0.119565 m3
Otros - ID de anfitrión: Muro básico: F3.2; Altura de extremo inicial: 2.2 m; Familia: Ventana 1 hoja: VE1_140 x 140 cm; Familia y tipo: Ventana 1 hoja: VE1_140 x 140 cm; ID de tipo: Ventana 1 hoja: VE1_140 x 140 cm; Tipo: Ventana 1 hoja: VE1_140 x 140 cm
Proceso por fases - Fase de creación: Nueva construcción
Restricciones - Altura de antepecho: 0.8 m
Name (Ventana 1 hoja:VE1_140 x 140 cm:...) | In | Marca | Nivel
189963 | 01.AR.PLANTA BAJA ACAB.SUELO | 2 | Nivel: 01.AR.PLANTA BAJA ACAB.SUELO
190006 | 01.AR.PLANTA BAJA ACAB.SUELO | 3 | Nivel: 01.AR.PLANTA BAJA ACAB.SUELO
190048 | 01.AR.PLANTA BAJA ACAB.SUELO | 4 | Nivel: 01.AR.PLANTA BAJA ACAB.SUELO
190117 | 01.AR.PLANTA BAJA ACAB.SUELO | 5 | Nivel: 01.AR.PLANTA BAJA ACAB.SUELO
190376 | 02.AR.PLANTA PRIMERA ACAB. SUELO | 10 | Nivel: 02.AR.PLANTA PRIMERA ACAB. SUELO
190377 | 02.AR.PLANTA PRIMERA ACAB. SUELO | 11 | Nivel: 02.AR.PLANTA PRIMERA ACAB. SUELO
190378 | 02.AR.PLANTA PRIMERA ACAB. SUELO | 12 | Nivel: 02.AR.PLANTA PRIMERA ACAB. SUELO
190379 | 02.AR.PLANTA PRIMERA ACAB. SUELO | 13 | Nivel: 02.AR.PLANTA PRIMERA ACAB. SUELO
191451 | 02.AR.PLANTA PRIMERA ACAB. SUELO | 21 | Nivel: 02.AR.PLANTA PRIMERA ACAB. SUELO

# IfcWindow: VE1_160 x 160 cm (8)
Type - ParameterTakesPrecedence: no; Sizeable: no; Material: negro, Vidrio, Dark Oak
Type - Construcción - Cierre de muro: Por anfitrión
Type - Cotas - Altura: 1.6 m; Anchura: 1.6 m
Type - Datos de identidad - Imagen de tipo: Imagen ráster: W 632.jpg; Descripción: 60 mm, 3 sistemas del perfil de la cámara Apoyo de la PCR Soportar todas las condiciones climáticas Max Heat - aislamiento acústico y agua Con la PCR, no hay necesidad adicional de la zona de metal de refuerzo 32 mm de acristalamiento Desplazamiento Tipo de guillotina Canal de drenaje de agua Gama de colores laminada Su calidad está acreditada por certificado internacional; Marca de tipo: 20; Nombre de tipo: VE1_160 x 160 cm; Número OmniClass: 23.30.20.00; Título OmniClass: Windows
Type - Otros - Categoría: Ventanas; Altura de antepecho por defecto: 0.8 m; Nombre de familia: Ventana 1 hoja
Type - Propiedades analíticas - Construcción analítica: <Ninguno>
OverallHeight: 1.6 m; OverallWidth: 1.6 m
Pset_WindowCommon - IsExternal: yes; Reference: VE1_160 x 160 cm
Cotas - Altura superior: 2.4 m; Área: 3.58901 m2; Volumen: 0.14678 m3
Otros - ID de anfitrión: Muro básico: F3.2; Altura de extremo inicial: 2.4 m; Familia: Ventana 1 hoja: VE1_160 x 160 cm; Familia y tipo: Ventana 1 hoja: VE1_160 x 160 cm; ID de tipo: Ventana 1 hoja: VE1_160 x 160 cm; Tipo: Ventana 1 hoja: VE1_160 x 160 cm
Proceso por fases - Fase de creación: Nueva construcción
Restricciones - Altura de antepecho: 0.8 m
Name (Ventana 1 hoja:VE1_160 x 160 cm:...) | In | Marca | Nivel
190170 | 01.AR.PLANTA BAJA ACAB.SUELO | 6 | Nivel: 01.AR.PLANTA BAJA ACAB.SUELO
190211 | 01.AR.PLANTA BAJA ACAB.SUELO | 7 | Nivel: 01.AR.PLANTA BAJA ACAB.SUELO
190258 | 01.AR.PLANTA BAJA ACAB.SUELO | 8 | Nivel: 01.AR.PLANTA BAJA ACAB.SUELO
190297 | 01.AR.PLANTA BAJA ACAB.SUELO | 9 | Nivel: 01.AR.PLANTA BAJA ACAB.SUELO
190380 | 02.AR.PLANTA PRIMERA ACAB. SUELO | 14 | Nivel: 02.AR.PLANTA PRIMERA ACAB. SUELO
190381 | 02.AR.PLANTA PRIMERA ACAB. SUELO | 15 | Nivel: 02.AR.PLANTA PRIMERA ACAB. SUELO
190398 | 02.AR.PLANTA PRIMERA ACAB. SUELO | 16 | Nivel: 02.AR.PLANTA PRIMERA ACAB. SUELO
191426 | 01.AR.PLANTA BAJA ACAB.SUELO | 20 | Nivel: 01.AR.PLANTA BAJA ACAB.SUELO
